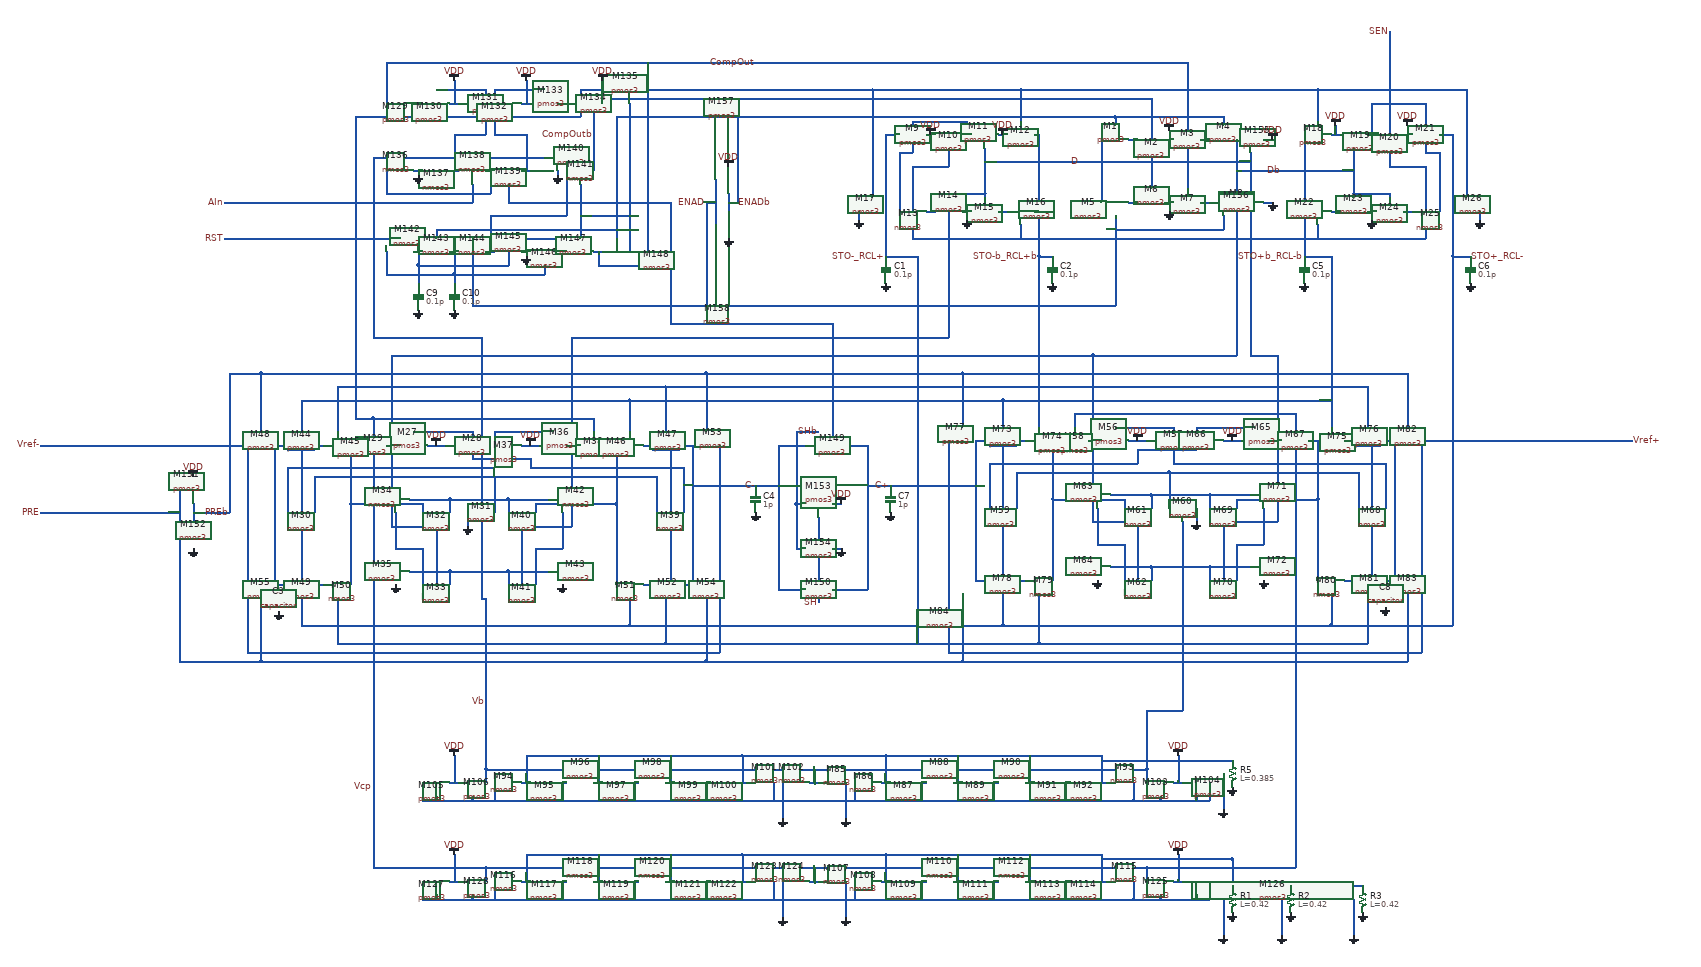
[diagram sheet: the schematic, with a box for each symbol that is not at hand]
v {xschem version=3.4.3 file_version=1.2
}
G {}
K {}
V {}
S {}
E {}
N 2570 -1810 2590 -1810 {
lab=#net1}
N 2650 -1810 2670 -1810 {
lab=VDD}
N 2730 -1810 2750 -1810 {
lab=#net2}
N 2570 -1670 2590 -1670 {
lab=#net3}
N 2650 -1670 2670 -1670 {
lab=GND}
N 2730 -1670 2750 -1670 {
lab=#net4}
N 2620 -1780 2620 -1700 {
lab=CompOutb}
N 2700 -1780 2700 -1700 {
lab=CompOut}
N 2660 -1830 2660 -1810 {
lab=VDD}
N 2660 -1670 2660 -1650 {
lab=GND}
N 2540 -1860 2540 -1840 {
lab=ENADb}
N 2540 -1640 2540 -1600 {
lab=ENAD}
N 2510 -1810 2510 -1670 {
lab=D}
N 2810 -1810 2810 -1670 {
lab=Db}
N 2120 -1820 2140 -1820 {
lab=VDD}
N 2200 -1820 2220 -1820 {
lab=#net5}
N 2280 -1820 2300 -1820 {
lab=VDD}
N 2090 -1790 2090 -1780 {
lab=#net5}
N 2120 -1650 2140 -1650 {
lab=#net6}
N 2200 -1650 2220 -1650 {
lab=GND}
N 2280 -1650 2300 -1650 {
lab=#net7}
N 2210 -1650 2210 -1630 {
lab=GND}
N 1970 -1650 1970 -1630 {
lab=GND}
N 2170 -1690 2170 -1680 {
lab=D}
N 2170 -1690 2250 -1690 {
lab=D}
N 2250 -1690 2250 -1680 {
lab=D}
N 2090 -1620 2090 -1590 {
lab=SEN}
N 2090 -1590 2330 -1590 {
lab=SEN}
N 2330 -1620 2330 -1590 {
lab=SEN}
N 2030 -1820 2030 -1650 {
lab=STO-_RCL+}
N 2060 -1780 2060 -1650 {
lab=#net5}
N 2060 -1780 2090 -1780 {
lab=#net5}
N 2030 -1820 2060 -1820 {
lab=STO-_RCL+}
N 2250 -1790 2250 -1690 {
lab=D}
N 2090 -1750 2090 -1620 {
lab=SEN}
N 2090 -1750 2170 -1750 {
lab=SEN}
N 2170 -1790 2170 -1750 {
lab=SEN}
N 2000 -1920 2000 -1680 {
lab=Vcp}
N 2000 -1920 2330 -1920 {
lab=Vcp}
N 2330 -1920 2330 -1850 {
lab=Vcp}
N 2030 -1650 2030 -1550 {
lab=STO-_RCL+}
N 3020 -1820 3040 -1820 {
lab=VDD}
N 3100 -1820 3120 -1820 {
lab=#net8}
N 3180 -1820 3200 -1820 {
lab=VDD}
N 3030 -1840 3030 -1820 {
lab=VDD}
N 3190 -1840 3190 -1820 {
lab=VDD}
N 3020 -1650 3040 -1650 {
lab=#net9}
N 3100 -1650 3120 -1650 {
lab=GND}
N 3180 -1650 3200 -1650 {
lab=#net10}
N 3110 -1650 3110 -1630 {
lab=GND}
N 3070 -1690 3070 -1680 {
lab=Db}
N 3070 -1690 3150 -1690 {
lab=Db}
N 3150 -1690 3150 -1680 {
lab=Db}
N 2990 -1620 2990 -1590 {
lab=SEN}
N 2990 -1590 3230 -1590 {
lab=SEN}
N 3230 -1620 3230 -1590 {
lab=SEN}
N 3110 -1890 3110 -1820 {
lab=#net8}
N 3350 -1650 3350 -1630 {
lab=GND}
N 3110 -1890 3230 -1890 {
lab=#net8}
N 3230 -1890 3230 -1790 {
lab=#net8}
N 3260 -1820 3290 -1820 {
lab=STO+_RCL-}
N 3290 -1820 3290 -1650 {
lab=STO+_RCL-}
N 3290 -1650 3290 -1550 {
lab=STO+_RCL-}
N 2960 -1650 2960 -1550 {
lab=STO+b_RCL-b}
N 3070 -1790 3070 -1690 {
lab=Db}
N 3230 -1790 3230 -1780 {
lab=#net8}
N 3260 -1780 3260 -1650 {
lab=#net8}
N 3230 -1780 3260 -1780 {
lab=#net8}
N 3230 -1750 3230 -1620 {
lab=SEN}
N 3150 -1750 3230 -1750 {
lab=SEN}
N 3150 -1790 3150 -1750 {
lab=SEN}
N 3320 -1910 3320 -1680 {
lab=Vcp}
N 3320 -1920 3320 -1910 {
lab=Vcp}
N 2990 -1920 3320 -1920 {
lab=Vcp}
N 2990 -1920 2990 -1850 {
lab=Vcp}
N 2960 -1820 2960 -1650 {
lab=STO+b_RCL-b}
N 2810 -1740 3070 -1740 {
lab=Db}
N 2330 -1920 2990 -1920 {
lab=Vcp}
N 2330 -1590 2990 -1590 {
lab=SEN}
N 1010 -1130 1050 -1130 {
lab=VDD}
N 980 -1160 1080 -1160 {
lab=#net11}
N 1030 -950 1030 -820 {
lab=Db}
N 1060 -1010 1060 -980 {
lab=#net12}
N 970 -1010 1060 -1010 {
lab=#net12}
N 970 -850 1060 -850 {
lab=#net13}
N 1060 -850 1060 -820 {
lab=#net13}
N 940 -980 940 -900 {
lab=#net14}
N 940 -900 1000 -900 {
lab=#net14}
N 1220 -1130 1260 -1130 {
lab=VDD}
N 1190 -1160 1290 -1160 {
lab=#net15}
N 1320 -1130 1350 -1130 {
lab=#net16}
N 1220 -950 1220 -820 {
lab=D}
N 1190 -1010 1280 -1010 {
lab=#net12}
N 1190 -850 1280 -850 {
lab=#net13}
N 1310 -980 1310 -900 {
lab=#net17}
N 1250 -900 1310 -900 {
lab=#net17}
N 700 -1120 760 -1120 {
lab=#net18}
N 760 -1130 760 -1120 {
lab=#net18}
N 700 -830 700 -820 {
lab=#net18}
N 700 -830 760 -830 {
lab=#net18}
N 760 -830 760 -820 {
lab=#net18}
N 730 -1120 730 -1020 {
lab=#net18}
N 730 -1020 730 -830 {
lab=#net18}
N 1510 -1130 1510 -1120 {
lab=C-}
N 1510 -1120 1570 -1120 {
lab=C-}
N 1570 -1130 1570 -1120 {
lab=C-}
N 1510 -830 1510 -820 {
lab=C-}
N 1510 -830 1570 -830 {
lab=C-}
N 1570 -830 1570 -820 {
lab=C-}
N 1550 -1120 1550 -1020 {
lab=C-}
N 1550 -1020 1550 -830 {
lab=C-}
N 760 -1130 780 -1130 {
lab=#net18}
N 760 -820 780 -820 {
lab=#net18}
N 1490 -1130 1510 -1130 {
lab=C-}
N 1490 -820 1510 -820 {
lab=C-}
N 1430 -1130 1430 -1040 {
lab=#net19}
N 1430 -960 1430 -820 {
lab=#net19}
N 1250 -1000 1250 -980 {
lab=#net19}
N 1250 -1000 1430 -1000 {
lab=#net19}
N 1430 -1040 1430 -1000 {
lab=#net19}
N 1000 -1000 1000 -980 {
lab=#net20}
N 840 -1000 1000 -1000 {
lab=#net20}
N 840 -1130 840 -1000 {
lab=#net20}
N 840 -1000 840 -820 {
lab=#net20}
N 1430 -1000 1430 -960 {
lab=#net19}
N 840 -1130 860 -1130 {
lab=#net20}
N 760 -1080 980 -1080 {
lab=#net15}
N 1290 -1080 1520 -1080 {
lab=#net11}
N 1080 -1160 1110 -1160 {
lab=#net11}
N 1110 -1160 1110 -1130 {
lab=#net11}
N 1160 -1160 1160 -1130 {
lab=#net15}
N 1160 -1160 1190 -1160 {
lab=#net15}
N 670 -1130 670 -820 {
lab=#net18}
N 1600 -1130 1600 -820 {
lab=C-}
N 610 -1130 610 -820 {
lab=Vref-}
N 1660 -1130 1660 -820 {
lab=Vref-}
N 1190 -850 1190 -820 {
lab=#net13}
N 1190 -1010 1190 -980 {
lab=#net12}
N 700 -1080 760 -1080 {
lab=#net15}
N 700 -1080 700 -980 {
lab=#net15}
N 1520 -1080 1580 -1080 {
lab=#net11}
N 1580 -1080 1580 -980 {
lab=#net11}
N 760 -1060 760 -980 {
lab=#net21}
N 760 -1060 1100 -1060 {
lab=#net21}
N 1100 -1060 1520 -1060 {
lab=#net21}
N 1520 -1060 1520 -980 {
lab=#net21}
N 1000 -900 1000 -820 {
lab=#net14}
N 1250 -900 1250 -820 {
lab=#net17}
N 1030 -820 1030 -790 {
lab=Db}
N 1220 -820 1220 -790 {
lab=D}
N 1130 -950 1130 -790 {
lab=Vb}
N 1410 -1130 1430 -1130 {
lab=#net19}
N 700 -1130 700 -1120 {
lab=#net18}
N 670 -1130 700 -1130 {
lab=#net18}
N 670 -820 700 -820 {
lab=#net18}
N 1570 -1130 1600 -1130 {
lab=C-}
N 1570 -820 1600 -820 {
lab=C-}
N 1060 -1010 1190 -1010 {
lab=#net12}
N 1060 -850 1190 -850 {
lab=#net13}
N 2570 -1140 2610 -1140 {
lab=VDD}
N 2540 -1170 2640 -1170 {
lab=#net22}
N 2480 -1140 2510 -1140 {
lab=#net23}
N 2590 -960 2590 -830 {
lab=Db}
N 2620 -1020 2620 -990 {
lab=#net24}
N 2530 -1020 2620 -1020 {
lab=#net24}
N 2530 -860 2620 -860 {
lab=#net25}
N 2620 -860 2620 -830 {
lab=#net25}
N 2500 -990 2500 -910 {
lab=#net26}
N 2500 -910 2560 -910 {
lab=#net26}
N 2780 -1140 2820 -1140 {
lab=VDD}
N 2750 -1170 2850 -1170 {
lab=#net27}
N 2880 -1140 2910 -1140 {
lab=#net28}
N 2780 -960 2780 -830 {
lab=D}
N 2750 -1020 2840 -1020 {
lab=#net24}
N 2750 -860 2840 -860 {
lab=#net25}
N 2870 -990 2870 -910 {
lab=#net29}
N 2810 -910 2870 -910 {
lab=#net29}
N 2260 -1130 2320 -1130 {
lab=C+}
N 2320 -1140 2320 -1130 {
lab=C+}
N 2260 -840 2260 -830 {
lab=C+}
N 2260 -840 2320 -840 {
lab=C+}
N 2320 -840 2320 -830 {
lab=C+}
N 2290 -1130 2290 -1030 {
lab=C+}
N 2290 -1030 2290 -840 {
lab=C+}
N 3070 -1140 3070 -1130 {
lab=#net30}
N 3070 -1130 3130 -1130 {
lab=#net30}
N 3130 -1140 3130 -1130 {
lab=#net30}
N 3070 -840 3070 -830 {
lab=#net30}
N 3070 -840 3130 -840 {
lab=#net30}
N 3130 -840 3130 -830 {
lab=#net30}
N 3110 -1130 3110 -1030 {
lab=#net30}
N 3110 -1030 3110 -840 {
lab=#net30}
N 2320 -1140 2340 -1140 {
lab=C+}
N 2320 -830 2340 -830 {
lab=C+}
N 3050 -1140 3070 -1140 {
lab=#net30}
N 3050 -830 3070 -830 {
lab=#net30}
N 2990 -1140 2990 -1050 {
lab=#net31}
N 2990 -970 2990 -830 {
lab=#net31}
N 2810 -1010 2810 -990 {
lab=#net31}
N 2810 -1010 2990 -1010 {
lab=#net31}
N 2990 -1050 2990 -1010 {
lab=#net31}
N 2560 -1010 2560 -990 {
lab=#net32}
N 2400 -1010 2560 -1010 {
lab=#net32}
N 2400 -1140 2400 -1010 {
lab=#net32}
N 2400 -1010 2400 -830 {
lab=#net32}
N 2990 -1010 2990 -970 {
lab=#net31}
N 2400 -1140 2420 -1140 {
lab=#net32}
N 2320 -1090 2540 -1090 {
lab=#net27}
N 2850 -1090 3080 -1090 {
lab=#net22}
N 2640 -1170 2670 -1170 {
lab=#net22}
N 2670 -1170 2670 -1140 {
lab=#net22}
N 2720 -1170 2720 -1140 {
lab=#net27}
N 2720 -1170 2750 -1170 {
lab=#net27}
N 2230 -1140 2230 -830 {
lab=C+}
N 3160 -1140 3160 -830 {
lab=#net30}
N 2170 -1140 2170 -830 {
lab=Vref+}
N 3220 -1140 3220 -830 {
lab=Vref+}
N 2750 -860 2750 -830 {
lab=#net25}
N 2750 -1020 2750 -990 {
lab=#net24}
N 2260 -1090 2320 -1090 {
lab=#net27}
N 2260 -1090 2260 -990 {
lab=#net27}
N 3080 -1090 3140 -1090 {
lab=#net22}
N 3140 -1090 3140 -990 {
lab=#net22}
N 2320 -1070 2320 -990 {
lab=#net33}
N 2320 -1070 2660 -1070 {
lab=#net33}
N 2660 -1070 2660 -990 {
lab=#net33}
N 2660 -1070 3080 -1070 {
lab=#net33}
N 3080 -1070 3080 -990 {
lab=#net33}
N 2560 -910 2560 -830 {
lab=#net26}
N 2810 -910 2810 -830 {
lab=#net29}
N 2590 -830 2590 -800 {
lab=Db}
N 2780 -830 2780 -800 {
lab=D}
N 2690 -960 2690 -800 {
lab=Vb}
N 2970 -1140 2990 -1140 {
lab=#net31}
N 2260 -1140 2260 -1130 {
lab=C+}
N 2230 -1140 2260 -1140 {
lab=C+}
N 2230 -830 2260 -830 {
lab=C+}
N 3130 -1140 3160 -1140 {
lab=#net30}
N 3130 -830 3160 -830 {
lab=#net30}
N 2620 -1020 2750 -1020 {
lab=#net24}
N 2620 -860 2750 -860 {
lab=#net25}
N 2020 -380 2040 -380 {
lab=#net34}
N 2100 -380 2120 -380 {
lab=#net35}
N 2180 -380 2200 -380 {
lab=#net34}
N 2260 -380 2280 -380 {
lab=#net35}
N 2340 -380 2360 -380 {
lab=#net34}
N 2420 -380 2440 -380 {
lab=#net35}
N 2500 -380 2520 -380 {
lab=#net34}
N 1220 -380 1240 -380 {
lab=#net34}
N 1300 -380 1320 -380 {
lab=#net35}
N 1380 -380 1400 -380 {
lab=#net34}
N 1460 -380 1480 -380 {
lab=#net35}
N 1540 -380 1560 -380 {
lab=#net34}
N 1620 -380 1640 -380 {
lab=#net35}
N 1700 -380 1720 -380 {
lab=#net34}
N 1860 -380 1880 -380 {
lab=Vb}
N 1190 -410 2550 -410 {
lab=Vb}
N 1780 -380 1780 -340 {
lab=#net35}
N 1160 -340 1780 -340 {
lab=#net35}
N 1160 -380 1160 -340 {
lab=#net35}
N 1470 -380 1470 -340 {
lab=#net35}
N 1310 -380 1310 -340 {
lab=#net35}
N 1630 -380 1630 -340 {
lab=#net35}
N 1230 -440 1230 -380 {
lab=#net34}
N 1230 -440 1710 -440 {
lab=#net34}
N 1710 -440 1710 -380 {
lab=#net34}
N 1550 -440 1550 -380 {
lab=#net34}
N 1390 -440 1390 -380 {
lab=#net34}
N 1960 -380 1960 -340 {
lab=#net35}
N 1960 -340 2580 -340 {
lab=#net35}
N 2580 -380 2580 -340 {
lab=#net35}
N 2270 -380 2270 -340 {
lab=#net35}
N 2110 -380 2110 -340 {
lab=#net35}
N 2430 -380 2430 -340 {
lab=#net35}
N 2030 -440 2030 -380 {
lab=#net34}
N 2030 -440 2510 -440 {
lab=#net34}
N 2510 -440 2510 -380 {
lab=#net34}
N 2350 -440 2350 -380 {
lab=#net34}
N 2190 -440 2190 -380 {
lab=#net34}
N 1710 -440 2030 -440 {
lab=#net34}
N 1780 -340 1960 -340 {
lab=#net35}
N 1870 -410 1870 -380 {
lab=Vb}
N 1800 -380 1800 -300 {
lab=GND}
N 1940 -380 1940 -300 {
lab=GND}
N 2670 -380 2690 -380 {
lab=VDD}
N 1060 -380 1080 -380 {
lab=VDD}
N 1070 -440 1070 -380 {
lab=VDD}
N 2680 -440 2680 -380 {
lab=VDD}
N 1140 -410 1140 -380 {
lab=Vb}
N 1140 -410 1190 -410 {
lab=Vb}
N 1110 -350 1110 -340 {
lab=#net35}
N 1110 -340 1160 -340 {
lab=#net35}
N 2640 -350 2640 -340 {
lab=#net35}
N 2580 -340 2640 -340 {
lab=#net35}
N 2610 -410 2610 -380 {
lab=Vb}
N 2550 -410 2610 -410 {
lab=Vb}
N 2640 -340 2750 -340 {
lab=#net35}
N 2720 -350 2720 -340 {
lab=#net35}
N 2750 -380 2750 -340 {
lab=#net35}
N 1000 -340 1110 -340 {
lab=#net35}
N 1000 -380 1000 -340 {
lab=#net35}
N 1030 -350 1030 -340 {
lab=#net35}
N 2510 -430 2800 -430 {
lab=#net34}
N 2020 -160 2040 -160 {
lab=#net36}
N 2100 -160 2120 -160 {
lab=#net37}
N 2180 -160 2200 -160 {
lab=#net36}
N 2260 -160 2280 -160 {
lab=#net37}
N 2340 -160 2360 -160 {
lab=#net36}
N 2420 -160 2440 -160 {
lab=#net37}
N 2500 -160 2520 -160 {
lab=#net36}
N 1220 -160 1240 -160 {
lab=#net36}
N 1300 -160 1320 -160 {
lab=#net37}
N 1380 -160 1400 -160 {
lab=#net36}
N 1460 -160 1480 -160 {
lab=#net37}
N 1540 -160 1560 -160 {
lab=#net36}
N 1620 -160 1640 -160 {
lab=#net37}
N 1700 -160 1720 -160 {
lab=#net36}
N 1860 -160 1880 -160 {
lab=Vcp}
N 1190 -190 2550 -190 {
lab=Vcp}
N 1780 -160 1780 -120 {
lab=#net37}
N 1160 -120 1780 -120 {
lab=#net37}
N 1160 -160 1160 -120 {
lab=#net37}
N 1470 -160 1470 -120 {
lab=#net37}
N 1310 -160 1310 -120 {
lab=#net37}
N 1630 -160 1630 -120 {
lab=#net37}
N 1230 -220 1230 -160 {
lab=#net36}
N 1230 -220 1710 -220 {
lab=#net36}
N 1710 -220 1710 -160 {
lab=#net36}
N 1550 -220 1550 -160 {
lab=#net36}
N 1390 -220 1390 -160 {
lab=#net36}
N 1960 -160 1960 -120 {
lab=#net37}
N 1960 -120 2580 -120 {
lab=#net37}
N 2580 -160 2580 -120 {
lab=#net37}
N 2270 -160 2270 -120 {
lab=#net37}
N 2110 -160 2110 -120 {
lab=#net37}
N 2430 -160 2430 -120 {
lab=#net37}
N 2030 -220 2030 -160 {
lab=#net36}
N 2030 -220 2510 -220 {
lab=#net36}
N 2510 -220 2510 -160 {
lab=#net36}
N 2350 -220 2350 -160 {
lab=#net36}
N 2190 -220 2190 -160 {
lab=#net36}
N 1710 -220 2030 -220 {
lab=#net36}
N 1780 -120 1960 -120 {
lab=#net37}
N 1870 -190 1870 -160 {
lab=Vcp}
N 1800 -160 1800 -80 {
lab=GND}
N 1940 -160 1940 -80 {
lab=GND}
N 2670 -160 2690 -160 {
lab=VDD}
N 1060 -160 1080 -160 {
lab=VDD}
N 1070 -220 1070 -160 {
lab=VDD}
N 2680 -220 2680 -160 {
lab=VDD}
N 1140 -190 1140 -160 {
lab=Vcp}
N 1140 -190 1190 -190 {
lab=Vcp}
N 1110 -130 1110 -120 {
lab=#net37}
N 1110 -120 1160 -120 {
lab=#net37}
N 2640 -130 2640 -120 {
lab=#net37}
N 2580 -120 2640 -120 {
lab=#net37}
N 2610 -190 2610 -160 {
lab=Vcp}
N 2550 -190 2610 -190 {
lab=Vcp}
N 2640 -120 2750 -120 {
lab=#net37}
N 2720 -130 2720 -120 {
lab=#net37}
N 2750 -160 2750 -120 {
lab=#net37}
N 1000 -120 1110 -120 {
lab=#net37}
N 1000 -160 1000 -120 {
lab=#net37}
N 1030 -130 1030 -120 {
lab=#net37}
N 2510 -210 2800 -210 {
lab=#net36}
N 2610 -480 2610 -410 {
lab=Vb}
N 980 -1890 1000 -1890 {
lab=#net38}
N 1060 -1890 1080 -1890 {
lab=VDD}
N 1220 -1890 1240 -1890 {
lab=VDD}
N 1300 -1890 1320 -1890 {
lab=#net39}
N 1030 -1920 1110 -1920 {
lab=#net40}
N 1190 -1920 1270 -1920 {
lab=#net41}
N 1140 -1920 1140 -1890 {
lab=#net40}
N 1110 -1920 1140 -1920 {
lab=#net40}
N 1160 -1920 1160 -1890 {
lab=#net41}
N 1160 -1920 1190 -1920 {
lab=#net41}
N 950 -1860 1350 -1860 {
lab=Vcp}
N 980 -1740 1000 -1740 {
lab=GND}
N 1140 -1740 1160 -1740 {
lab=#net42}
N 1060 -1740 1080 -1740 {
lab=#net40}
N 1220 -1740 1240 -1740 {
lab=#net41}
N 980 -1560 1000 -1560 {
lab=#net43}
N 1140 -1560 1160 -1560 {
lab=#net44}
N 1060 -1560 1080 -1560 {
lab=#net45}
N 1220 -1560 1240 -1560 {
lab=GND}
N 1300 -1560 1320 -1560 {
lab=#net43}
N 1380 -1560 1400 -1560 {
lab=CompOut}
N 1380 -1890 1380 -1740 {
lab=CompOutb}
N 1460 -1690 1460 -1560 {
lab=#net46}
N 1430 -1860 1430 -1590 {
lab=ENADb}
N 1460 -1890 1460 -1690 {
lab=#net46}
N 1350 -1710 1350 -1590 {
lab=#net46}
N 1350 -1640 1460 -1640 {
lab=#net46}
N 1150 -1640 1150 -1560 {
lab=#net44}
N 1150 -1640 1320 -1640 {
lab=#net44}
N 1320 -1740 1320 -1640 {
lab=#net44}
N 920 -1560 920 -1530 {
lab=#net45}
N 920 -1530 920 -1510 {
lab=#net45}
N 920 -1510 1070 -1510 {
lab=#net45}
N 1190 -1590 1310 -1590 {
lab=#net43}
N 1310 -1590 1310 -1560 {
lab=#net43}
N 1070 -1510 1270 -1510 {
lab=#net45}
N 1270 -1530 1270 -1510 {
lab=#net45}
N 1230 -1560 1230 -1550 {
lab=GND}
N 1190 -1590 1190 -1530 {
lab=#net43}
N 990 -1530 1190 -1530 {
lab=#net43}
N 1070 -1560 1070 -1510 {
lab=#net45}
N 1070 -1510 1070 -1490 {
lab=#net45}
N 990 -1560 990 -1530 {
lab=#net43}
N 990 -1530 990 -1490 {
lab=#net43}
N 1140 -1890 1140 -1820 {
lab=#net40}
N 1070 -1820 1140 -1820 {
lab=#net40}
N 1070 -1820 1070 -1740 {
lab=#net40}
N 1160 -1890 1160 -1820 {
lab=#net41}
N 1160 -1820 1230 -1820 {
lab=#net41}
N 1230 -1820 1230 -1740 {
lab=#net41}
N 990 -1740 990 -1730 {
lab=GND}
N 920 -1740 920 -1690 {
lab=#net42}
N 920 -1690 1150 -1690 {
lab=#net42}
N 1150 -1740 1150 -1690 {
lab=#net42}
N 1300 -1740 1300 -1730 {
lab=GND}
N 950 -1770 1270 -1770 {
lab=Vb}
N 1070 -1940 1070 -1890 {
lab=VDD}
N 1230 -1940 1230 -1890 {
lab=VDD}
N 1400 -1940 1400 -1890 {
lab=VDD}
N 1030 -1610 1030 -1590 {
lab=ENADb}
N 1030 -1610 1430 -1610 {
lab=ENADb}
N 920 -1130 950 -1130 {
lab=#net47}
N 490 -1000 490 -960 {
lab=PREb}
N 460 -1030 460 -930 {
lab=PRE}
N 490 -980 510 -980 {
lab=PREb}
N 1680 -1690 1680 -1650 {
lab=ENADb}
N 1650 -1720 1650 -1620 {
lab=ENAD}
N 1630 -1670 1650 -1670 {
lab=ENAD}
N 1680 -1670 1700 -1670 {
lab=ENADb}
N 560 -1590 950 -1590 {
lab=RST}
N 150 -1130 610 -1130 {
lab=Vref-}
N 3220 -1140 3690 -1140 {
lab=Vref+}
N 890 -1190 890 -1160 {
lab=Vcp}
N 890 -1190 1380 -1190 {
lab=Vcp}
N 1380 -1190 1380 -1160 {
lab=Vcp}
N 890 -1860 950 -1860 {
lab=Vcp}
N 2450 -1200 2450 -1170 {
lab=Vcp}
N 2450 -1200 2940 -1200 {
lab=Vcp}
N 2940 -1200 2940 -1170 {
lab=Vcp}
N 890 -190 1140 -190 {
lab=Vcp}
N 1350 -1920 1350 -1860 {
lab=Vcp}
N 1350 -1920 2000 -1920 {
lab=Vcp}
N 2800 -210 2800 -150 {
lab=#net36}
N 2610 -190 2940 -190 {
lab=Vcp}
N 890 -1160 890 -190 {
lab=Vcp}
N 2940 -1170 2940 -190 {
lab=Vcp}
N 980 -1080 1160 -1080 {
lab=#net15}
N 1160 -1130 1160 -1080 {
lab=#net15}
N 1240 -1080 1290 -1080 {
lab=#net11}
N 1240 -1100 1240 -1080 {
lab=#net11}
N 1110 -1100 1240 -1100 {
lab=#net11}
N 1110 -1130 1110 -1100 {
lab=#net11}
N 2670 -1090 2850 -1090 {
lab=#net22}
N 2670 -1140 2670 -1090 {
lab=#net22}
N 2540 -1090 2590 -1090 {
lab=#net27}
N 2590 -1120 2590 -1090 {
lab=#net27}
N 2590 -1120 2720 -1120 {
lab=#net27}
N 2720 -1140 2720 -1120 {
lab=#net27}
N 3150 -2050 3150 -1790 {
lab=SEN}
N 1880 -970 1880 -780 {
lab=SH}
N 1830 -900 1850 -900 {
lab=SHb}
N 1830 -1000 1830 -900 {
lab=SHb}
N 1830 -1000 1850 -1000 {
lab=SHb}
N 1830 -1160 1830 -1000 {
lab=SHb}
N 1830 -1160 1880 -1160 {
lab=SHb}
N 1790 -1130 1790 -1060 {
lab=C-}
N 1790 -1130 1850 -1130 {
lab=C-}
N 1790 -1060 1790 -810 {
lab=C-}
N 1790 -810 1850 -810 {
lab=C-}
N 1910 -1000 1930 -1000 {
lab=VDD}
N 1910 -900 1930 -900 {
lab=GND}
N 1910 -810 1990 -810 {
lab=C+}
N 1990 -1130 1990 -810 {
lab=C+}
N 1600 -1040 1790 -1040 {
lab=C-}
N 2720 -990 2720 -960 {
lab=GND}
N 2690 -800 2690 -540 {
lab=Vb}
N 2610 -540 2690 -540 {
lab=Vb}
N 2610 -540 2610 -480 {
lab=Vb}
N 1100 -980 1100 -950 {
lab=GND}
N 1140 -790 1140 -410 {
lab=Vb}
N 1130 -790 1140 -790 {
lab=Vb}
N 1110 -1710 1110 -1670 {
lab=AIn}
N 560 -1670 1110 -1670 {
lab=AIn}
N 1190 -1710 1190 -1670 {
lab=C+}
N 1190 -1670 1550 -1670 {
lab=C+}
N 3290 -1550 3330 -1550 {
lab=STO+_RCL-}
N 3290 -1550 3290 -770 {
lab=STO+_RCL-}
N 1910 -1130 1990 -1130 {
lab=C+}
N 1990 -1040 2230 -1040 {
lab=C+}
N 3290 -770 3290 -730 {
lab=STO+_RCL-}
N 3020 -730 3290 -730 {
lab=STO+_RCL-}
N 3020 -800 3020 -730 {
lab=STO+_RCL-}
N 2290 -730 3020 -730 {
lab=STO+_RCL-}
N 2290 -800 2290 -730 {
lab=STO+_RCL-}
N 1460 -730 2290 -730 {
lab=STO+_RCL-}
N 1460 -790 1460 -730 {
lab=STO+_RCL-}
N 730 -730 1460 -730 {
lab=STO+_RCL-}
N 730 -790 730 -730 {
lab=STO+_RCL-}
N 1130 -1370 1130 -950 {
lab=Vb}
N 910 -1370 1130 -1370 {
lab=Vb}
N 890 -1370 910 -1370 {
lab=Vb}
N 890 -1770 890 -1370 {
lab=Vb}
N 890 -1770 950 -1770 {
lab=Vb}
N 850 -1860 890 -1860 {
lab=Vcp}
N 850 -1860 850 -1190 {
lab=Vcp}
N 850 -1190 890 -1190 {
lab=Vcp}
N 810 -790 810 -690 {
lab=STO-_RCL+}
N 810 -690 1540 -690 {
lab=STO-_RCL+}
N 1540 -790 1540 -690 {
lab=STO-_RCL+}
N 1540 -690 2370 -690 {
lab=STO-_RCL+}
N 2370 -800 2370 -690 {
lab=STO-_RCL+}
N 2370 -690 3100 -690 {
lab=STO-_RCL+}
N 3100 -800 3100 -690 {
lab=STO-_RCL+}
N 2100 -1550 2100 -690 {
lab=STO-_RCL+}
N 2030 -1550 2100 -1550 {
lab=STO-_RCL+}
N 920 -1980 920 -1890 {
lab=CompOut}
N 920 -1980 2700 -1980 {
lab=CompOut}
N 2700 -1980 2700 -1780 {
lab=CompOut}
N 1390 -1530 1500 -1530 {
lab=CompOut}
N 1500 -1980 1500 -1530 {
lab=CompOut}
N 1390 -1560 1390 -1530 {
lab=CompOut}
N 1380 -1900 1380 -1890 {
lab=CompOutb}
N 1380 -1900 2620 -1900 {
lab=CompOutb}
N 2620 -1900 2620 -1780 {
lab=CompOutb}
N 3020 -1550 3020 -1170 {
lab=STO+b_RCL-b}
N 2960 -1550 3020 -1550 {
lab=STO+b_RCL-b}
N 2290 -1230 2290 -1170 {
lab=STO+b_RCL-b}
N 2290 -1230 3020 -1230 {
lab=STO+b_RCL-b}
N 1460 -1230 2290 -1230 {
lab=STO+b_RCL-b}
N 1460 -1230 1460 -1160 {
lab=STO+b_RCL-b}
N 730 -1230 1460 -1230 {
lab=STO+b_RCL-b}
N 730 -1230 730 -1160 {
lab=STO+b_RCL-b}
N 2360 -1260 3100 -1260 {
lab=STO-b_RCL+b}
N 3100 -1260 3100 -1170 {
lab=STO-b_RCL+b}
N 1540 -1260 2360 -1260 {
lab=STO-b_RCL+b}
N 1540 -1260 1540 -1160 {
lab=STO-b_RCL+b}
N 810 -1260 1540 -1260 {
lab=STO-b_RCL+b}
N 810 -1260 810 -1160 {
lab=STO-b_RCL+b}
N 640 -790 640 -650 {
lab=PRE}
N 640 -650 1630 -650 {
lab=PRE}
N 1630 -790 1630 -650 {
lab=PRE}
N 460 -930 460 -650 {
lab=PRE}
N 460 -650 640 -650 {
lab=PRE}
N 150 -980 460 -980 {
lab=PRE}
N 1630 -650 2200 -650 {
lab=PRE}
N 2200 -800 2200 -650 {
lab=PRE}
N 2200 -650 3190 -650 {
lab=PRE}
N 3190 -800 3190 -650 {
lab=PRE}
N 640 -1290 640 -1160 {
lab=PREb}
N 640 -1290 1630 -1290 {
lab=PREb}
N 1630 -1290 1630 -1160 {
lab=PREb}
N 1630 -1290 2200 -1290 {
lab=PREb}
N 2200 -1290 2200 -1170 {
lab=PREb}
N 2200 -1290 3190 -1290 {
lab=PREb}
N 3190 -1290 3190 -1170 {
lab=PREb}
N 570 -1290 640 -1290 {
lab=PREb}
N 570 -1290 570 -980 {
lab=PREb}
N 510 -980 570 -980 {
lab=PREb}
N 610 -820 610 -670 {
lab=Vref-}
N 610 -670 1660 -670 {
lab=Vref-}
N 1660 -820 1660 -670 {
lab=Vref-}
N 2170 -830 2170 -670 {
lab=Vref+}
N 2170 -670 3220 -670 {
lab=Vref+}
N 3220 -830 3220 -670 {
lab=Vref+}
N 2090 -1850 2090 -1790 {
lab=#net5}
N 2090 -1850 2210 -1850 {
lab=#net5}
N 2210 -1850 2210 -1820 {
lab=#net5}
N 1430 -1860 2540 -1860 {
lab=ENADb}
N 2780 -1860 2780 -1840 {
lab=ENADb}
N 2540 -1860 2780 -1860 {
lab=ENADb}
N 2540 -1600 2540 -1440 {
lab=ENAD}
N 1110 -1440 2540 -1440 {
lab=ENAD}
N 1110 -1590 1110 -1440 {
lab=ENAD}
N 2540 -1610 2780 -1610 {
lab=ENAD}
N 2780 -1640 2780 -1610 {
lab=ENAD}
N 1550 -1670 1550 -1400 {
lab=C+}
N 1550 -1400 1910 -1400 {
lab=C+}
N 1910 -1400 1910 -1130 {
lab=C+}
N 1700 -1860 1700 -1670 {
lab=ENADb}
N 1630 -1670 1630 -1440 {
lab=ENAD}
N 2370 -1260 2370 -1170 {
lab=STO-b_RCL+b}
N 2370 -1550 2370 -1260 {
lab=STO-b_RCL+b}
N 2370 -1820 2370 -1550 {
lab=STO-b_RCL+b}
N 2360 -1820 2370 -1820 {
lab=STO-b_RCL+b}
N 2360 -1650 2370 -1650 {
lab=STO-b_RCL+b}
N 2370 -1550 2400 -1550 {
lab=STO-b_RCL+b}
N 1160 -1060 1160 -980 {
lab=#net21}
N 2870 -1810 2890 -1810 {
lab=VDD}
N 2870 -1670 2890 -1670 {
lab=GND}
N 2840 -1780 2840 -1700 {
lab=D}
N 2510 -1760 2840 -1760 {
lab=D}
N 2250 -1760 2510 -1760 {
lab=D}
N 1220 -950 1330 -950 {
lab=D}
N 930 -950 1030 -950 {
lab=Db}
N 930 -1330 930 -950 {
lab=Db}
N 2490 -960 2590 -960 {
lab=Db}
N 2780 -960 2900 -960 {
lab=D}
N 2900 -1330 2900 -960 {
lab=D}
N 2840 -1330 2900 -1330 {
lab=D}
N 2840 -1700 2840 -1330 {
lab=D}
N 930 -1330 1220 -1330 {
lab=Db}
N 1220 -1330 2490 -1330 {
lab=Db}
N 2490 -1330 2810 -1330 {
lab=Db}
N 2810 -1670 2810 -1330 {
lab=Db}
N 2490 -1330 2490 -960 {
lab=Db}
N 1330 -1370 1330 -950 {
lab=D}
N 1330 -1370 2170 -1370 {
lab=D}
N 2170 -1680 2170 -1370 {
lab=D}
N 2800 -210 2800 -150 {
lab=#net3}
N 2780 -400 2780 -370 {
lab=GND}
N 2780 -370 2780 -320 {
lab=GND}
N 2780 -90 2780 -40 {
lab=GND}
N 2780 -120 2780 -90 {
lab=GND}
N 2910 -90 2910 -40 {
lab=GND}
N 2910 -120 2910 -90 {
lab=GND}
N 3070 -90 3070 -40 {
lab=GND}
N 3070 -120 3070 -90 {
lab=GND}
N 2800 -150 2930 -150 {
lab=#net3}
N 2930 -150 3090 -150 {
lab=#net3}
C {madvlsi/pmos3.sym} 2540 -1810 1 0 {name=M1
L=0.15
W=1
body=VDD
nf=1
mult=1
ad="'int((nf+1)/2) * W/nf * 0.29'" 
pd="'2*int((nf+1)/2) * (W/nf + 0.29)'"
as="'int((nf+2)/2) * W/nf * 0.29'" 
ps="'2*int((nf+2)/2) * (W/nf + 0.29)'"
nrd="'0.29 / W'" nrs="'0.29 / W'"
sa=0 sb=0 sd=0
model=pfet_01v8
spiceprefix=X
}
C {madvlsi/pmos3.sym} 2620 -1810 3 0 {name=M2
L=0.15
W=1
body=VDD
nf=1
mult=1
ad="'int((nf+1)/2) * W/nf * 0.29'" 
pd="'2*int((nf+1)/2) * (W/nf + 0.29)'"
as="'int((nf+2)/2) * W/nf * 0.29'" 
ps="'2*int((nf+2)/2) * (W/nf + 0.29)'"
nrd="'0.29 / W'" nrs="'0.29 / W'"
sa=0 sb=0 sd=0
model=pfet_01v8
spiceprefix=X
}
C {madvlsi/pmos3.sym} 2700 -1810 3 0 {name=M3
L=0.15
W=1
body=VDD
nf=1
mult=1
ad="'int((nf+1)/2) * W/nf * 0.29'" 
pd="'2*int((nf+1)/2) * (W/nf + 0.29)'"
as="'int((nf+2)/2) * W/nf * 0.29'" 
ps="'2*int((nf+2)/2) * (W/nf + 0.29)'"
nrd="'0.29 / W'" nrs="'0.29 / W'"
sa=0 sb=0 sd=0
model=pfet_01v8
spiceprefix=X
}
C {madvlsi/pmos3.sym} 2780 -1810 1 0 {name=M4
L=0.15
W=1
body=VDD
nf=1
mult=1
ad="'int((nf+1)/2) * W/nf * 0.29'" 
pd="'2*int((nf+1)/2) * (W/nf + 0.29)'"
as="'int((nf+2)/2) * W/nf * 0.29'" 
ps="'2*int((nf+2)/2) * (W/nf + 0.29)'"
nrd="'0.29 / W'" nrs="'0.29 / W'"
sa=0 sb=0 sd=0
model=pfet_01v8
spiceprefix=X
}
C {madvlsi/nmos3.sym} 2540 -1670 3 0 {name=M5
L=0.15
W=1
body=GND
nf=1
mult=1
ad="'int((nf+1)/2) * W/nf * 0.29'" 
pd="'2*int((nf+1)/2) * (W/nf + 0.29)'"
as="'int((nf+2)/2) * W/nf * 0.29'" 
ps="'2*int((nf+2)/2) * (W/nf + 0.29)'"
nrd="'0.29 / W'" nrs="'0.29 / W'"
sa=0 sb=0 sd=0
model=nfet_01v8
spiceprefix=X
}
C {madvlsi/nmos3.sym} 2620 -1670 1 0 {name=M6
L=0.15
W=1
body=GND
nf=1
mult=1
ad="'int((nf+1)/2) * W/nf * 0.29'" 
pd="'2*int((nf+1)/2) * (W/nf + 0.29)'"
as="'int((nf+2)/2) * W/nf * 0.29'" 
ps="'2*int((nf+2)/2) * (W/nf + 0.29)'"
nrd="'0.29 / W'" nrs="'0.29 / W'"
sa=0 sb=0 sd=0
model=nfet_01v8
spiceprefix=X
}
C {madvlsi/nmos3.sym} 2700 -1670 1 0 {name=M7
L=0.15
W=1
body=GND
nf=1
mult=1
ad="'int((nf+1)/2) * W/nf * 0.29'" 
pd="'2*int((nf+1)/2) * (W/nf + 0.29)'"
as="'int((nf+2)/2) * W/nf * 0.29'" 
ps="'2*int((nf+2)/2) * (W/nf + 0.29)'"
nrd="'0.29 / W'" nrs="'0.29 / W'"
sa=0 sb=0 sd=0
model=nfet_01v8
spiceprefix=X
}
C {madvlsi/nmos3.sym} 2780 -1670 3 0 {name=M8
L=0.15
W=1
body=GND
nf=1
mult=1
ad="'int((nf+1)/2) * W/nf * 0.29'" 
pd="'2*int((nf+1)/2) * (W/nf + 0.29)'"
as="'int((nf+2)/2) * W/nf * 0.29'" 
ps="'2*int((nf+2)/2) * (W/nf + 0.29)'"
nrd="'0.29 / W'" nrs="'0.29 / W'"
sa=0 sb=0 sd=0
model=nfet_01v8
spiceprefix=X
}
C {madvlsi/vdd.sym} 2660 -1830 0 0 {name=l1 lab=VDD}
C {madvlsi/gnd.sym} 2660 -1650 0 0 {name=l2 lab=GND}
C {devices/lab_pin.sym} 2460 -1760 1 0 {name=p5 sig_type=std_logic lab=D}
C {devices/lab_pin.sym} 2910 -1740 1 0 {name=p6 sig_type=std_logic lab=Db}
C {madvlsi/pmos3.sym} 2090 -1820 3 0 {name=M9
L=0.15
W=1
body=VDD
nf=1
mult=1
ad="'int((nf+1)/2) * W/nf * 0.29'" 
pd="'2*int((nf+1)/2) * (W/nf + 0.29)'"
as="'int((nf+2)/2) * W/nf * 0.29'" 
ps="'2*int((nf+2)/2) * (W/nf + 0.29)'"
nrd="'0.29 / W'" nrs="'0.29 / W'"
sa=0 sb=0 sd=0
model=pfet_01v8
spiceprefix=X
}
C {madvlsi/pmos3.sym} 2170 -1820 3 0 {name=M10
L=0.15
W=1
body=VDD
nf=1
mult=1
ad="'int((nf+1)/2) * W/nf * 0.29'" 
pd="'2*int((nf+1)/2) * (W/nf + 0.29)'"
as="'int((nf+2)/2) * W/nf * 0.29'" 
ps="'2*int((nf+2)/2) * (W/nf + 0.29)'"
nrd="'0.29 / W'" nrs="'0.29 / W'"
sa=0 sb=0 sd=0
model=pfet_01v8
spiceprefix=X
}
C {madvlsi/pmos3.sym} 2250 -1820 3 0 {name=M11
L=0.15
W=1
body=VDD
nf=1
mult=1
ad="'int((nf+1)/2) * W/nf * 0.29'" 
pd="'2*int((nf+1)/2) * (W/nf + 0.29)'"
as="'int((nf+2)/2) * W/nf * 0.29'" 
ps="'2*int((nf+2)/2) * (W/nf + 0.29)'"
nrd="'0.29 / W'" nrs="'0.29 / W'"
sa=0 sb=0 sd=0
model=pfet_01v8
spiceprefix=X
}
C {madvlsi/pmos3.sym} 2330 -1820 1 0 {name=M12
L=0.15
W=1
body=VDD
nf=1
mult=1
ad="'int((nf+1)/2) * W/nf * 0.29'" 
pd="'2*int((nf+1)/2) * (W/nf + 0.29)'"
as="'int((nf+2)/2) * W/nf * 0.29'" 
ps="'2*int((nf+2)/2) * (W/nf + 0.29)'"
nrd="'0.29 / W'" nrs="'0.29 / W'"
sa=0 sb=0 sd=0
model=pfet_01v8
spiceprefix=X
}
C {madvlsi/vdd.sym} 2130 -1820 0 0 {name=l5 lab=VDD}
C {madvlsi/vdd.sym} 2290 -1820 0 0 {name=l6 lab=VDD}
C {madvlsi/nmos3.sym} 2090 -1650 3 0 {name=M13
L=0.15
W=1
body=GND
nf=1
mult=1
ad="'int((nf+1)/2) * W/nf * 0.29'" 
pd="'2*int((nf+1)/2) * (W/nf + 0.29)'"
as="'int((nf+2)/2) * W/nf * 0.29'" 
ps="'2*int((nf+2)/2) * (W/nf + 0.29)'"
nrd="'0.29 / W'" nrs="'0.29 / W'"
sa=0 sb=0 sd=0
model=nfet_01v8
spiceprefix=X
}
C {madvlsi/nmos3.sym} 2170 -1650 1 0 {name=M14
L=0.15
W=1
body=GND
nf=1
mult=1
ad="'int((nf+1)/2) * W/nf * 0.29'" 
pd="'2*int((nf+1)/2) * (W/nf + 0.29)'"
as="'int((nf+2)/2) * W/nf * 0.29'" 
ps="'2*int((nf+2)/2) * (W/nf + 0.29)'"
nrd="'0.29 / W'" nrs="'0.29 / W'"
sa=0 sb=0 sd=0
model=nfet_01v8
spiceprefix=X
}
C {madvlsi/nmos3.sym} 2250 -1650 1 0 {name=M15
L=0.15
W=1
body=GND
nf=1
mult=1
ad="'int((nf+1)/2) * W/nf * 0.29'" 
pd="'2*int((nf+1)/2) * (W/nf + 0.29)'"
as="'int((nf+2)/2) * W/nf * 0.29'" 
ps="'2*int((nf+2)/2) * (W/nf + 0.29)'"
nrd="'0.29 / W'" nrs="'0.29 / W'"
sa=0 sb=0 sd=0
model=nfet_01v8
spiceprefix=X
}
C {madvlsi/nmos3.sym} 2330 -1650 3 0 {name=M16
L=0.15
W=1
body=GND
nf=1
mult=1
ad="'int((nf+1)/2) * W/nf * 0.29'" 
pd="'2*int((nf+1)/2) * (W/nf + 0.29)'"
as="'int((nf+2)/2) * W/nf * 0.29'" 
ps="'2*int((nf+2)/2) * (W/nf + 0.29)'"
nrd="'0.29 / W'" nrs="'0.29 / W'"
sa=0 sb=0 sd=0
model=nfet_01v8
spiceprefix=X
}
C {madvlsi/gnd.sym} 2210 -1630 0 0 {name=l7 lab=GND}
C {madvlsi/nmos3.sym} 2000 -1650 1 0 {name=M17
L=0.15
W=1
body=GND
nf=1
mult=1
ad="'int((nf+1)/2) * W/nf * 0.29'" 
pd="'2*int((nf+1)/2) * (W/nf + 0.29)'"
as="'int((nf+2)/2) * W/nf * 0.29'" 
ps="'2*int((nf+2)/2) * (W/nf + 0.29)'"
nrd="'0.29 / W'" nrs="'0.29 / W'"
sa=0 sb=0 sd=0
model=nfet_01v8
spiceprefix=X
}
C {madvlsi/gnd.sym} 1970 -1630 0 0 {name=l8 lab=GND}
C {madvlsi/capacitor.sym} 2030 -1520 0 0 {name=C1
value=0.1p
m=1}
C {madvlsi/gnd.sym} 2030 -1490 0 0 {name=l9 lab=GND}
C {madvlsi/capacitor.sym} 2400 -1520 0 0 {name=C2
value=0.1p
m=1}
C {madvlsi/gnd.sym} 2400 -1490 0 0 {name=l10 lab=GND}
C {devices/lab_pin.sym} 2030 -1550 0 0 {name=p10 sig_type=std_logic lab=STO-_RCL+}
C {devices/lab_pin.sym} 2370 -1550 0 0 {name=p11 sig_type=std_logic lab=STO-b_RCL+b}
C {devices/lab_pin.sym} 3150 -2050 1 0 {name=p13 sig_type=std_logic lab=SEN}
C {madvlsi/pmos3.sym} 2990 -1820 1 0 {name=M18
L=0.15
W=1
body=VDD
nf=1
mult=1
ad="'int((nf+1)/2) * W/nf * 0.29'" 
pd="'2*int((nf+1)/2) * (W/nf + 0.29)'"
as="'int((nf+2)/2) * W/nf * 0.29'" 
ps="'2*int((nf+2)/2) * (W/nf + 0.29)'"
nrd="'0.29 / W'" nrs="'0.29 / W'"
sa=0 sb=0 sd=0
model=pfet_01v8
spiceprefix=X
}
C {madvlsi/pmos3.sym} 3070 -1820 3 0 {name=M19
L=0.15
W=1
body=VDD
nf=1
mult=1
ad="'int((nf+1)/2) * W/nf * 0.29'" 
pd="'2*int((nf+1)/2) * (W/nf + 0.29)'"
as="'int((nf+2)/2) * W/nf * 0.29'" 
ps="'2*int((nf+2)/2) * (W/nf + 0.29)'"
nrd="'0.29 / W'" nrs="'0.29 / W'"
sa=0 sb=0 sd=0
model=pfet_01v8
spiceprefix=X
}
C {madvlsi/pmos3.sym} 3150 -1820 3 0 {name=M20
L=0.15
W=1
body=VDD
nf=1
mult=1
ad="'int((nf+1)/2) * W/nf * 0.29'" 
pd="'2*int((nf+1)/2) * (W/nf + 0.29)'"
as="'int((nf+2)/2) * W/nf * 0.29'" 
ps="'2*int((nf+2)/2) * (W/nf + 0.29)'"
nrd="'0.29 / W'" nrs="'0.29 / W'"
sa=0 sb=0 sd=0
model=pfet_01v8
spiceprefix=X
}
C {madvlsi/pmos3.sym} 3230 -1820 3 0 {name=M21
L=0.15
W=1
body=VDD
nf=1
mult=1
ad="'int((nf+1)/2) * W/nf * 0.29'" 
pd="'2*int((nf+1)/2) * (W/nf + 0.29)'"
as="'int((nf+2)/2) * W/nf * 0.29'" 
ps="'2*int((nf+2)/2) * (W/nf + 0.29)'"
nrd="'0.29 / W'" nrs="'0.29 / W'"
sa=0 sb=0 sd=0
model=pfet_01v8
spiceprefix=X
}
C {madvlsi/vdd.sym} 3030 -1840 0 0 {name=l11 lab=VDD}
C {madvlsi/vdd.sym} 3190 -1840 0 0 {name=l12 lab=VDD}
C {madvlsi/nmos3.sym} 2990 -1650 3 0 {name=M22
L=0.15
W=1
body=GND
nf=1
mult=1
ad="'int((nf+1)/2) * W/nf * 0.29'" 
pd="'2*int((nf+1)/2) * (W/nf + 0.29)'"
as="'int((nf+2)/2) * W/nf * 0.29'" 
ps="'2*int((nf+2)/2) * (W/nf + 0.29)'"
nrd="'0.29 / W'" nrs="'0.29 / W'"
sa=0 sb=0 sd=0
model=nfet_01v8
spiceprefix=X
}
C {madvlsi/nmos3.sym} 3070 -1650 1 0 {name=M23
L=0.15
W=1
body=GND
nf=1
mult=1
ad="'int((nf+1)/2) * W/nf * 0.29'" 
pd="'2*int((nf+1)/2) * (W/nf + 0.29)'"
as="'int((nf+2)/2) * W/nf * 0.29'" 
ps="'2*int((nf+2)/2) * (W/nf + 0.29)'"
nrd="'0.29 / W'" nrs="'0.29 / W'"
sa=0 sb=0 sd=0
model=nfet_01v8
spiceprefix=X
}
C {madvlsi/nmos3.sym} 3150 -1650 1 0 {name=M24
L=0.15
W=1
body=GND
nf=1
mult=1
ad="'int((nf+1)/2) * W/nf * 0.29'" 
pd="'2*int((nf+1)/2) * (W/nf + 0.29)'"
as="'int((nf+2)/2) * W/nf * 0.29'" 
ps="'2*int((nf+2)/2) * (W/nf + 0.29)'"
nrd="'0.29 / W'" nrs="'0.29 / W'"
sa=0 sb=0 sd=0
model=nfet_01v8
spiceprefix=X
}
C {madvlsi/nmos3.sym} 3230 -1650 3 0 {name=M25
L=0.15
W=1
body=GND
nf=1
mult=1
ad="'int((nf+1)/2) * W/nf * 0.29'" 
pd="'2*int((nf+1)/2) * (W/nf + 0.29)'"
as="'int((nf+2)/2) * W/nf * 0.29'" 
ps="'2*int((nf+2)/2) * (W/nf + 0.29)'"
nrd="'0.29 / W'" nrs="'0.29 / W'"
sa=0 sb=0 sd=0
model=nfet_01v8
spiceprefix=X
}
C {madvlsi/gnd.sym} 3110 -1630 0 0 {name=l13 lab=GND}
C {madvlsi/nmos3.sym} 3320 -1650 1 0 {name=M26
L=0.15
W=1
body=GND
nf=1
mult=1
ad="'int((nf+1)/2) * W/nf * 0.29'" 
pd="'2*int((nf+1)/2) * (W/nf + 0.29)'"
as="'int((nf+2)/2) * W/nf * 0.29'" 
ps="'2*int((nf+2)/2) * (W/nf + 0.29)'"
nrd="'0.29 / W'" nrs="'0.29 / W'"
sa=0 sb=0 sd=0
model=nfet_01v8
spiceprefix=X
}
C {madvlsi/gnd.sym} 3350 -1630 0 0 {name=l14 lab=GND}
C {madvlsi/capacitor.sym} 2960 -1520 0 0 {name=C5
value=0.1p
m=1}
C {madvlsi/gnd.sym} 2960 -1490 0 0 {name=l15 lab=GND}
C {madvlsi/capacitor.sym} 3330 -1520 0 0 {name=C6
value=0.1p
m=1}
C {madvlsi/gnd.sym} 3330 -1490 0 0 {name=l18 lab=GND}
C {devices/lab_pin.sym} 2960 -1550 0 0 {name=p16 sig_type=std_logic lab=STO+b_RCL-b}
C {devices/lab_pin.sym} 3330 -1550 2 0 {name=p17 sig_type=std_logic lab=STO+_RCL-}
C {madvlsi/pmos3.sym} 980 -1130 3 1 {name=M27
L=0.15
W=1
body=VDD
nf=1
mult=1
ad="'int((nf+1)/2) * W/nf * 0.29'" 
pd="'2*int((nf+1)/2) * (W/nf + 0.29)'"
as="'int((nf+2)/2) * W/nf * 0.29'" 
ps="'2*int((nf+2)/2) * (W/nf + 0.29)'"
nrd="'0.29 / W'" nrs="'0.29 / W'"
sa=0 sb=0 sd=0
model=pfet_01v8
spiceprefix=X
}
C {madvlsi/pmos3.sym} 1080 -1130 3 1 {name=M28
L=0.15
W=1
body=VDD
nf=1
mult=1
ad="'int((nf+1)/2) * W/nf * 0.29'" 
pd="'2*int((nf+1)/2) * (W/nf + 0.29)'"
as="'int((nf+2)/2) * W/nf * 0.29'" 
ps="'2*int((nf+2)/2) * (W/nf + 0.29)'"
nrd="'0.29 / W'" nrs="'0.29 / W'"
sa=0 sb=0 sd=0
model=pfet_01v8
spiceprefix=X
}
C {madvlsi/pmos3.sym} 890 -1130 1 0 {name=M29
L=0.15
W=1
body=VDD
nf=1
mult=1
ad="'int((nf+1)/2) * W/nf * 0.29'" 
pd="'2*int((nf+1)/2) * (W/nf + 0.29)'"
as="'int((nf+2)/2) * W/nf * 0.29'" 
ps="'2*int((nf+2)/2) * (W/nf + 0.29)'"
nrd="'0.29 / W'" nrs="'0.29 / W'"
sa=0 sb=0 sd=0
model=pfet_01v8
spiceprefix=X
}
C {madvlsi/nmos3.sym} 730 -980 3 1 {name=M30
L=0.15
W=1
body=GND
nf=1
mult=1
ad="'int((nf+1)/2) * W/nf * 0.29'" 
pd="'2*int((nf+1)/2) * (W/nf + 0.29)'"
as="'int((nf+2)/2) * W/nf * 0.29'" 
ps="'2*int((nf+2)/2) * (W/nf + 0.29)'"
nrd="'0.29 / W'" nrs="'0.29 / W'"
sa=0 sb=0 sd=0
model=nfet_01v8
spiceprefix=X
}
C {madvlsi/nmos3.sym} 1130 -980 3 0 {name=M31
L=0.15
W=1
body=GND
nf=1
mult=1
ad="'int((nf+1)/2) * W/nf * 0.29'" 
pd="'2*int((nf+1)/2) * (W/nf + 0.29)'"
as="'int((nf+2)/2) * W/nf * 0.29'" 
ps="'2*int((nf+2)/2) * (W/nf + 0.29)'"
nrd="'0.29 / W'" nrs="'0.29 / W'"
sa=0 sb=0 sd=0
model=nfet_01v8
spiceprefix=X
}
C {madvlsi/nmos3.sym} 1030 -980 1 1 {name=M32
L=0.15
W=1
body=GND
nf=1
mult=1
ad="'int((nf+1)/2) * W/nf * 0.29'" 
pd="'2*int((nf+1)/2) * (W/nf + 0.29)'"
as="'int((nf+2)/2) * W/nf * 0.29'" 
ps="'2*int((nf+2)/2) * (W/nf + 0.29)'"
nrd="'0.29 / W'" nrs="'0.29 / W'"
sa=0 sb=0 sd=0
model=nfet_01v8
spiceprefix=X
}
C {devices/lab_pin.sym} 1030 -790 3 0 {name=p12 sig_type=std_logic lab=Db}
C {madvlsi/nmos3.sym} 1030 -820 1 1 {name=M33
L=0.15
W=1
body=GND
nf=1
mult=1
ad="'int((nf+1)/2) * W/nf * 0.29'" 
pd="'2*int((nf+1)/2) * (W/nf + 0.29)'"
as="'int((nf+2)/2) * W/nf * 0.29'" 
ps="'2*int((nf+2)/2) * (W/nf + 0.29)'"
nrd="'0.29 / W'" nrs="'0.29 / W'"
sa=0 sb=0 sd=0
model=nfet_01v8
spiceprefix=X
}
C {madvlsi/nmos3.sym} 970 -980 3 1 {name=M34
L=0.15
W=1
body=GND
nf=1
mult=1
ad="'int((nf+1)/2) * W/nf * 0.29'" 
pd="'2*int((nf+1)/2) * (W/nf + 0.29)'"
as="'int((nf+2)/2) * W/nf * 0.29'" 
ps="'2*int((nf+2)/2) * (W/nf + 0.29)'"
nrd="'0.29 / W'" nrs="'0.29 / W'"
sa=0 sb=0 sd=0
model=nfet_01v8
spiceprefix=X
}
C {madvlsi/nmos3.sym} 970 -820 3 1 {name=M35
L=0.15
W=1
body=GND
nf=1
mult=1
ad="'int((nf+1)/2) * W/nf * 0.29'" 
pd="'2*int((nf+1)/2) * (W/nf + 0.29)'"
as="'int((nf+2)/2) * W/nf * 0.29'" 
ps="'2*int((nf+2)/2) * (W/nf + 0.29)'"
nrd="'0.29 / W'" nrs="'0.29 / W'"
sa=0 sb=0 sd=0
model=nfet_01v8
spiceprefix=X
}
C {madvlsi/pmos3.sym} 1290 -1130 1 0 {name=M36
L=0.15
W=1
body=VDD
nf=1
mult=1
ad="'int((nf+1)/2) * W/nf * 0.29'" 
pd="'2*int((nf+1)/2) * (W/nf + 0.29)'"
as="'int((nf+2)/2) * W/nf * 0.29'" 
ps="'2*int((nf+2)/2) * (W/nf + 0.29)'"
nrd="'0.29 / W'" nrs="'0.29 / W'"
sa=0 sb=0 sd=0
model=pfet_01v8
spiceprefix=X
}
C {madvlsi/pmos3.sym} 1190 -1130 1 0 {name=M37
L=0.15
W=1
body=VDD
nf=1
mult=1
ad="'int((nf+1)/2) * W/nf * 0.29'" 
pd="'2*int((nf+1)/2) * (W/nf + 0.29)'"
as="'int((nf+2)/2) * W/nf * 0.29'" 
ps="'2*int((nf+2)/2) * (W/nf + 0.29)'"
nrd="'0.29 / W'" nrs="'0.29 / W'"
sa=0 sb=0 sd=0
model=pfet_01v8
spiceprefix=X
}
C {madvlsi/pmos3.sym} 1380 -1130 3 1 {name=M38
L=0.15
W=1
body=VDD
nf=1
mult=1
ad="'int((nf+1)/2) * W/nf * 0.29'" 
pd="'2*int((nf+1)/2) * (W/nf + 0.29)'"
as="'int((nf+2)/2) * W/nf * 0.29'" 
ps="'2*int((nf+2)/2) * (W/nf + 0.29)'"
nrd="'0.29 / W'" nrs="'0.29 / W'"
sa=0 sb=0 sd=0
model=pfet_01v8
spiceprefix=X
}
C {madvlsi/nmos3.sym} 1550 -980 1 0 {name=M39
L=0.15
W=1
body=GND
nf=1
mult=1
ad="'int((nf+1)/2) * W/nf * 0.29'" 
pd="'2*int((nf+1)/2) * (W/nf + 0.29)'"
as="'int((nf+2)/2) * W/nf * 0.29'" 
ps="'2*int((nf+2)/2) * (W/nf + 0.29)'"
nrd="'0.29 / W'" nrs="'0.29 / W'"
sa=0 sb=0 sd=0
model=nfet_01v8
spiceprefix=X
}
C {madvlsi/nmos3.sym} 1220 -980 3 0 {name=M40
L=0.15
W=1
body=GND
nf=1
mult=1
ad="'int((nf+1)/2) * W/nf * 0.29'" 
pd="'2*int((nf+1)/2) * (W/nf + 0.29)'"
as="'int((nf+2)/2) * W/nf * 0.29'" 
ps="'2*int((nf+2)/2) * (W/nf + 0.29)'"
nrd="'0.29 / W'" nrs="'0.29 / W'"
sa=0 sb=0 sd=0
model=nfet_01v8
spiceprefix=X
}
C {devices/lab_pin.sym} 1220 -790 1 1 {name=p14 sig_type=std_logic lab=D}
C {madvlsi/nmos3.sym} 1220 -820 3 0 {name=M41
L=0.15
W=1
body=GND
nf=1
mult=1
ad="'int((nf+1)/2) * W/nf * 0.29'" 
pd="'2*int((nf+1)/2) * (W/nf + 0.29)'"
as="'int((nf+2)/2) * W/nf * 0.29'" 
ps="'2*int((nf+2)/2) * (W/nf + 0.29)'"
nrd="'0.29 / W'" nrs="'0.29 / W'"
sa=0 sb=0 sd=0
model=nfet_01v8
spiceprefix=X
}
C {madvlsi/nmos3.sym} 1280 -980 1 0 {name=M42
L=0.15
W=1
body=GND
nf=1
mult=1
ad="'int((nf+1)/2) * W/nf * 0.29'" 
pd="'2*int((nf+1)/2) * (W/nf + 0.29)'"
as="'int((nf+2)/2) * W/nf * 0.29'" 
ps="'2*int((nf+2)/2) * (W/nf + 0.29)'"
nrd="'0.29 / W'" nrs="'0.29 / W'"
sa=0 sb=0 sd=0
model=nfet_01v8
spiceprefix=X
}
C {madvlsi/nmos3.sym} 1280 -820 1 0 {name=M43
L=0.15
W=1
body=GND
nf=1
mult=1
ad="'int((nf+1)/2) * W/nf * 0.29'" 
pd="'2*int((nf+1)/2) * (W/nf + 0.29)'"
as="'int((nf+2)/2) * W/nf * 0.29'" 
ps="'2*int((nf+2)/2) * (W/nf + 0.29)'"
nrd="'0.29 / W'" nrs="'0.29 / W'"
sa=0 sb=0 sd=0
model=nfet_01v8
spiceprefix=X
}
C {madvlsi/pmos3.sym} 730 -1130 3 1 {name=M44
L=0.15
W=1
body=VDD
nf=1
mult=1
ad="'int((nf+1)/2) * W/nf * 0.29'" 
pd="'2*int((nf+1)/2) * (W/nf + 0.29)'"
as="'int((nf+2)/2) * W/nf * 0.29'" 
ps="'2*int((nf+2)/2) * (W/nf + 0.29)'"
nrd="'0.29 / W'" nrs="'0.29 / W'"
sa=0 sb=0 sd=0
model=pfet_01v8
spiceprefix=X
}
C {madvlsi/pmos3.sym} 810 -1130 3 1 {name=M45
L=0.15
W=1
body=VDD
nf=1
mult=1
ad="'int((nf+1)/2) * W/nf * 0.29'" 
pd="'2*int((nf+1)/2) * (W/nf + 0.29)'"
as="'int((nf+2)/2) * W/nf * 0.29'" 
ps="'2*int((nf+2)/2) * (W/nf + 0.29)'"
nrd="'0.29 / W'" nrs="'0.29 / W'"
sa=0 sb=0 sd=0
model=pfet_01v8
spiceprefix=X
}
C {madvlsi/pmos3.sym} 1460 -1130 3 1 {name=M46
L=0.15
W=1
body=VDD
nf=1
mult=1
ad="'int((nf+1)/2) * W/nf * 0.29'" 
pd="'2*int((nf+1)/2) * (W/nf + 0.29)'"
as="'int((nf+2)/2) * W/nf * 0.29'" 
ps="'2*int((nf+2)/2) * (W/nf + 0.29)'"
nrd="'0.29 / W'" nrs="'0.29 / W'"
sa=0 sb=0 sd=0
model=pfet_01v8
spiceprefix=X
}
C {madvlsi/pmos3.sym} 1540 -1130 3 1 {name=M47
L=0.15
W=1
body=VDD
nf=1
mult=1
ad="'int((nf+1)/2) * W/nf * 0.29'" 
pd="'2*int((nf+1)/2) * (W/nf + 0.29)'"
as="'int((nf+2)/2) * W/nf * 0.29'" 
ps="'2*int((nf+2)/2) * (W/nf + 0.29)'"
nrd="'0.29 / W'" nrs="'0.29 / W'"
sa=0 sb=0 sd=0
model=pfet_01v8
spiceprefix=X
}
C {madvlsi/pmos3.sym} 640 -1130 1 0 {name=M48
L=0.15
W=1
body=VDD
nf=1
mult=1
ad="'int((nf+1)/2) * W/nf * 0.29'" 
pd="'2*int((nf+1)/2) * (W/nf + 0.29)'"
as="'int((nf+2)/2) * W/nf * 0.29'" 
ps="'2*int((nf+2)/2) * (W/nf + 0.29)'"
nrd="'0.29 / W'" nrs="'0.29 / W'"
sa=0 sb=0 sd=0
model=pfet_01v8
spiceprefix=X
}
C {madvlsi/nmos3.sym} 730 -820 3 0 {name=M49
L=0.15
W=1
body=GND
nf=1
mult=1
ad="'int((nf+1)/2) * W/nf * 0.29'" 
pd="'2*int((nf+1)/2) * (W/nf + 0.29)'"
as="'int((nf+2)/2) * W/nf * 0.29'" 
ps="'2*int((nf+2)/2) * (W/nf + 0.29)'"
nrd="'0.29 / W'" nrs="'0.29 / W'"
sa=0 sb=0 sd=0
model=nfet_01v8
spiceprefix=X
}
C {madvlsi/nmos3.sym} 810 -820 3 0 {name=M50
L=0.15
W=1
body=GND
nf=1
mult=1
ad="'int((nf+1)/2) * W/nf * 0.29'" 
pd="'2*int((nf+1)/2) * (W/nf + 0.29)'"
as="'int((nf+2)/2) * W/nf * 0.29'" 
ps="'2*int((nf+2)/2) * (W/nf + 0.29)'"
nrd="'0.29 / W'" nrs="'0.29 / W'"
sa=0 sb=0 sd=0
model=nfet_01v8
spiceprefix=X
}
C {madvlsi/nmos3.sym} 1460 -820 3 0 {name=M51
L=0.15
W=1
body=GND
nf=1
mult=1
ad="'int((nf+1)/2) * W/nf * 0.29'" 
pd="'2*int((nf+1)/2) * (W/nf + 0.29)'"
as="'int((nf+2)/2) * W/nf * 0.29'" 
ps="'2*int((nf+2)/2) * (W/nf + 0.29)'"
nrd="'0.29 / W'" nrs="'0.29 / W'"
sa=0 sb=0 sd=0
model=nfet_01v8
spiceprefix=X
}
C {madvlsi/nmos3.sym} 1540 -820 3 0 {name=M52
L=0.15
W=1
body=GND
nf=1
mult=1
ad="'int((nf+1)/2) * W/nf * 0.29'" 
pd="'2*int((nf+1)/2) * (W/nf + 0.29)'"
as="'int((nf+2)/2) * W/nf * 0.29'" 
ps="'2*int((nf+2)/2) * (W/nf + 0.29)'"
nrd="'0.29 / W'" nrs="'0.29 / W'"
sa=0 sb=0 sd=0
model=nfet_01v8
spiceprefix=X
}
C {madvlsi/pmos3.sym} 1630 -1130 1 0 {name=M53
L=0.15
W=1
body=VDD
nf=1
mult=1
ad="'int((nf+1)/2) * W/nf * 0.29'" 
pd="'2*int((nf+1)/2) * (W/nf + 0.29)'"
as="'int((nf+2)/2) * W/nf * 0.29'" 
ps="'2*int((nf+2)/2) * (W/nf + 0.29)'"
nrd="'0.29 / W'" nrs="'0.29 / W'"
sa=0 sb=0 sd=0
model=pfet_01v8
spiceprefix=X
}
C {madvlsi/nmos3.sym} 1630 -820 3 0 {name=M54
L=0.15
W=1
body=GND
nf=1
mult=1
ad="'int((nf+1)/2) * W/nf * 0.29'" 
pd="'2*int((nf+1)/2) * (W/nf + 0.29)'"
as="'int((nf+2)/2) * W/nf * 0.29'" 
ps="'2*int((nf+2)/2) * (W/nf + 0.29)'"
nrd="'0.29 / W'" nrs="'0.29 / W'"
sa=0 sb=0 sd=0
model=nfet_01v8
spiceprefix=X
}
C {madvlsi/nmos3.sym} 640 -820 3 0 {name=M55
L=0.15
W=1
body=GND
nf=1
mult=1
ad="'int((nf+1)/2) * W/nf * 0.29'" 
pd="'2*int((nf+1)/2) * (W/nf + 0.29)'"
as="'int((nf+2)/2) * W/nf * 0.29'" 
ps="'2*int((nf+2)/2) * (W/nf + 0.29)'"
nrd="'0.29 / W'" nrs="'0.29 / W'"
sa=0 sb=0 sd=0
model=nfet_01v8
spiceprefix=X
}
C {devices/lab_pin.sym} 150 -1130 0 0 {name=p30 sig_type=std_logic lab=Vref-}
C {madvlsi/capacitor.sym} 680 -790 0 0 {name=C3
value=1p
m=1}
C {madvlsi/capacitor.sym} 1740 -1010 0 0 {name=C4
value=1p
m=1}
C {madvlsi/pmos3.sym} 2540 -1140 3 1 {name=M56
L=0.15
W=1
body=VDD
nf=1
mult=1
ad="'int((nf+1)/2) * W/nf * 0.29'" 
pd="'2*int((nf+1)/2) * (W/nf + 0.29)'"
as="'int((nf+2)/2) * W/nf * 0.29'" 
ps="'2*int((nf+2)/2) * (W/nf + 0.29)'"
nrd="'0.29 / W'" nrs="'0.29 / W'"
sa=0 sb=0 sd=0
model=pfet_01v8
spiceprefix=X
}
C {madvlsi/pmos3.sym} 2640 -1140 3 1 {name=M57
L=0.15
W=1
body=VDD
nf=1
mult=1
ad="'int((nf+1)/2) * W/nf * 0.29'" 
pd="'2*int((nf+1)/2) * (W/nf + 0.29)'"
as="'int((nf+2)/2) * W/nf * 0.29'" 
ps="'2*int((nf+2)/2) * (W/nf + 0.29)'"
nrd="'0.29 / W'" nrs="'0.29 / W'"
sa=0 sb=0 sd=0
model=pfet_01v8
spiceprefix=X
}
C {madvlsi/pmos3.sym} 2450 -1140 1 0 {name=M58
L=0.15
W=1
body=VDD
nf=1
mult=1
ad="'int((nf+1)/2) * W/nf * 0.29'" 
pd="'2*int((nf+1)/2) * (W/nf + 0.29)'"
as="'int((nf+2)/2) * W/nf * 0.29'" 
ps="'2*int((nf+2)/2) * (W/nf + 0.29)'"
nrd="'0.29 / W'" nrs="'0.29 / W'"
sa=0 sb=0 sd=0
model=pfet_01v8
spiceprefix=X
}
C {madvlsi/nmos3.sym} 2290 -990 3 1 {name=M59
L=0.15
W=1
body=GND
nf=1
mult=1
ad="'int((nf+1)/2) * W/nf * 0.29'" 
pd="'2*int((nf+1)/2) * (W/nf + 0.29)'"
as="'int((nf+2)/2) * W/nf * 0.29'" 
ps="'2*int((nf+2)/2) * (W/nf + 0.29)'"
nrd="'0.29 / W'" nrs="'0.29 / W'"
sa=0 sb=0 sd=0
model=nfet_01v8
spiceprefix=X
}
C {madvlsi/nmos3.sym} 2690 -990 3 0 {name=M60
L=0.15
W=1
body=GND
nf=1
mult=1
ad="'int((nf+1)/2) * W/nf * 0.29'" 
pd="'2*int((nf+1)/2) * (W/nf + 0.29)'"
as="'int((nf+2)/2) * W/nf * 0.29'" 
ps="'2*int((nf+2)/2) * (W/nf + 0.29)'"
nrd="'0.29 / W'" nrs="'0.29 / W'"
sa=0 sb=0 sd=0
model=nfet_01v8
spiceprefix=X
}
C {madvlsi/nmos3.sym} 2590 -990 1 1 {name=M61
L=0.15
W=1
body=GND
nf=1
mult=1
ad="'int((nf+1)/2) * W/nf * 0.29'" 
pd="'2*int((nf+1)/2) * (W/nf + 0.29)'"
as="'int((nf+2)/2) * W/nf * 0.29'" 
ps="'2*int((nf+2)/2) * (W/nf + 0.29)'"
nrd="'0.29 / W'" nrs="'0.29 / W'"
sa=0 sb=0 sd=0
model=nfet_01v8
spiceprefix=X
}
C {devices/lab_pin.sym} 2590 -800 3 0 {name=p37 sig_type=std_logic lab=Db}
C {madvlsi/nmos3.sym} 2590 -830 1 1 {name=M62
L=0.15
W=1
body=GND
nf=1
mult=1
ad="'int((nf+1)/2) * W/nf * 0.29'" 
pd="'2*int((nf+1)/2) * (W/nf + 0.29)'"
as="'int((nf+2)/2) * W/nf * 0.29'" 
ps="'2*int((nf+2)/2) * (W/nf + 0.29)'"
nrd="'0.29 / W'" nrs="'0.29 / W'"
sa=0 sb=0 sd=0
model=nfet_01v8
spiceprefix=X
}
C {madvlsi/nmos3.sym} 2530 -990 3 1 {name=M63
L=0.15
W=1
body=GND
nf=1
mult=1
ad="'int((nf+1)/2) * W/nf * 0.29'" 
pd="'2*int((nf+1)/2) * (W/nf + 0.29)'"
as="'int((nf+2)/2) * W/nf * 0.29'" 
ps="'2*int((nf+2)/2) * (W/nf + 0.29)'"
nrd="'0.29 / W'" nrs="'0.29 / W'"
sa=0 sb=0 sd=0
model=nfet_01v8
spiceprefix=X
}
C {madvlsi/nmos3.sym} 2530 -830 3 1 {name=M64
L=0.15
W=1
body=GND
nf=1
mult=1
ad="'int((nf+1)/2) * W/nf * 0.29'" 
pd="'2*int((nf+1)/2) * (W/nf + 0.29)'"
as="'int((nf+2)/2) * W/nf * 0.29'" 
ps="'2*int((nf+2)/2) * (W/nf + 0.29)'"
nrd="'0.29 / W'" nrs="'0.29 / W'"
sa=0 sb=0 sd=0
model=nfet_01v8
spiceprefix=X
}
C {madvlsi/pmos3.sym} 2850 -1140 1 0 {name=M65
L=0.15
W=1
body=VDD
nf=1
mult=1
ad="'int((nf+1)/2) * W/nf * 0.29'" 
pd="'2*int((nf+1)/2) * (W/nf + 0.29)'"
as="'int((nf+2)/2) * W/nf * 0.29'" 
ps="'2*int((nf+2)/2) * (W/nf + 0.29)'"
nrd="'0.29 / W'" nrs="'0.29 / W'"
sa=0 sb=0 sd=0
model=pfet_01v8
spiceprefix=X
}
C {madvlsi/pmos3.sym} 2750 -1140 1 0 {name=M66
L=0.15
W=1
body=VDD
nf=1
mult=1
ad="'int((nf+1)/2) * W/nf * 0.29'" 
pd="'2*int((nf+1)/2) * (W/nf + 0.29)'"
as="'int((nf+2)/2) * W/nf * 0.29'" 
ps="'2*int((nf+2)/2) * (W/nf + 0.29)'"
nrd="'0.29 / W'" nrs="'0.29 / W'"
sa=0 sb=0 sd=0
model=pfet_01v8
spiceprefix=X
}
C {madvlsi/pmos3.sym} 2940 -1140 3 1 {name=M67
L=0.15
W=1
body=VDD
nf=1
mult=1
ad="'int((nf+1)/2) * W/nf * 0.29'" 
pd="'2*int((nf+1)/2) * (W/nf + 0.29)'"
as="'int((nf+2)/2) * W/nf * 0.29'" 
ps="'2*int((nf+2)/2) * (W/nf + 0.29)'"
nrd="'0.29 / W'" nrs="'0.29 / W'"
sa=0 sb=0 sd=0
model=pfet_01v8
spiceprefix=X
}
C {madvlsi/nmos3.sym} 3110 -990 1 0 {name=M68
L=0.15
W=1
body=GND
nf=1
mult=1
ad="'int((nf+1)/2) * W/nf * 0.29'" 
pd="'2*int((nf+1)/2) * (W/nf + 0.29)'"
as="'int((nf+2)/2) * W/nf * 0.29'" 
ps="'2*int((nf+2)/2) * (W/nf + 0.29)'"
nrd="'0.29 / W'" nrs="'0.29 / W'"
sa=0 sb=0 sd=0
model=nfet_01v8
spiceprefix=X
}
C {madvlsi/nmos3.sym} 2780 -990 3 0 {name=M69
L=0.15
W=1
body=GND
nf=1
mult=1
ad="'int((nf+1)/2) * W/nf * 0.29'" 
pd="'2*int((nf+1)/2) * (W/nf + 0.29)'"
as="'int((nf+2)/2) * W/nf * 0.29'" 
ps="'2*int((nf+2)/2) * (W/nf + 0.29)'"
nrd="'0.29 / W'" nrs="'0.29 / W'"
sa=0 sb=0 sd=0
model=nfet_01v8
spiceprefix=X
}
C {devices/lab_pin.sym} 2780 -800 1 1 {name=p38 sig_type=std_logic lab=D}
C {madvlsi/nmos3.sym} 2780 -830 3 0 {name=M70
L=0.15
W=1
body=GND
nf=1
mult=1
ad="'int((nf+1)/2) * W/nf * 0.29'" 
pd="'2*int((nf+1)/2) * (W/nf + 0.29)'"
as="'int((nf+2)/2) * W/nf * 0.29'" 
ps="'2*int((nf+2)/2) * (W/nf + 0.29)'"
nrd="'0.29 / W'" nrs="'0.29 / W'"
sa=0 sb=0 sd=0
model=nfet_01v8
spiceprefix=X
}
C {madvlsi/nmos3.sym} 2840 -990 1 0 {name=M71
L=0.15
W=1
body=GND
nf=1
mult=1
ad="'int((nf+1)/2) * W/nf * 0.29'" 
pd="'2*int((nf+1)/2) * (W/nf + 0.29)'"
as="'int((nf+2)/2) * W/nf * 0.29'" 
ps="'2*int((nf+2)/2) * (W/nf + 0.29)'"
nrd="'0.29 / W'" nrs="'0.29 / W'"
sa=0 sb=0 sd=0
model=nfet_01v8
spiceprefix=X
}
C {madvlsi/nmos3.sym} 2840 -830 1 0 {name=M72
L=0.15
W=1
body=GND
nf=1
mult=1
ad="'int((nf+1)/2) * W/nf * 0.29'" 
pd="'2*int((nf+1)/2) * (W/nf + 0.29)'"
as="'int((nf+2)/2) * W/nf * 0.29'" 
ps="'2*int((nf+2)/2) * (W/nf + 0.29)'"
nrd="'0.29 / W'" nrs="'0.29 / W'"
sa=0 sb=0 sd=0
model=nfet_01v8
spiceprefix=X
}
C {madvlsi/pmos3.sym} 2290 -1140 3 1 {name=M73
L=0.15
W=1
body=VDD
nf=1
mult=1
ad="'int((nf+1)/2) * W/nf * 0.29'" 
pd="'2*int((nf+1)/2) * (W/nf + 0.29)'"
as="'int((nf+2)/2) * W/nf * 0.29'" 
ps="'2*int((nf+2)/2) * (W/nf + 0.29)'"
nrd="'0.29 / W'" nrs="'0.29 / W'"
sa=0 sb=0 sd=0
model=pfet_01v8
spiceprefix=X
}
C {madvlsi/pmos3.sym} 2370 -1140 3 1 {name=M74
L=0.15
W=1
body=VDD
nf=1
mult=1
ad="'int((nf+1)/2) * W/nf * 0.29'" 
pd="'2*int((nf+1)/2) * (W/nf + 0.29)'"
as="'int((nf+2)/2) * W/nf * 0.29'" 
ps="'2*int((nf+2)/2) * (W/nf + 0.29)'"
nrd="'0.29 / W'" nrs="'0.29 / W'"
sa=0 sb=0 sd=0
model=pfet_01v8
spiceprefix=X
}
C {madvlsi/pmos3.sym} 3020 -1140 3 1 {name=M75
L=0.15
W=1
body=VDD
nf=1
mult=1
ad="'int((nf+1)/2) * W/nf * 0.29'" 
pd="'2*int((nf+1)/2) * (W/nf + 0.29)'"
as="'int((nf+2)/2) * W/nf * 0.29'" 
ps="'2*int((nf+2)/2) * (W/nf + 0.29)'"
nrd="'0.29 / W'" nrs="'0.29 / W'"
sa=0 sb=0 sd=0
model=pfet_01v8
spiceprefix=X
}
C {madvlsi/pmos3.sym} 3100 -1140 3 1 {name=M76
L=0.15
W=1
body=VDD
nf=1
mult=1
ad="'int((nf+1)/2) * W/nf * 0.29'" 
pd="'2*int((nf+1)/2) * (W/nf + 0.29)'"
as="'int((nf+2)/2) * W/nf * 0.29'" 
ps="'2*int((nf+2)/2) * (W/nf + 0.29)'"
nrd="'0.29 / W'" nrs="'0.29 / W'"
sa=0 sb=0 sd=0
model=pfet_01v8
spiceprefix=X
}
C {madvlsi/pmos3.sym} 2200 -1140 1 0 {name=M77
L=0.15
W=1
body=VDD
nf=1
mult=1
ad="'int((nf+1)/2) * W/nf * 0.29'" 
pd="'2*int((nf+1)/2) * (W/nf + 0.29)'"
as="'int((nf+2)/2) * W/nf * 0.29'" 
ps="'2*int((nf+2)/2) * (W/nf + 0.29)'"
nrd="'0.29 / W'" nrs="'0.29 / W'"
sa=0 sb=0 sd=0
model=pfet_01v8
spiceprefix=X
}
C {madvlsi/nmos3.sym} 2290 -830 3 0 {name=M78
L=0.15
W=1
body=GND
nf=1
mult=1
ad="'int((nf+1)/2) * W/nf * 0.29'" 
pd="'2*int((nf+1)/2) * (W/nf + 0.29)'"
as="'int((nf+2)/2) * W/nf * 0.29'" 
ps="'2*int((nf+2)/2) * (W/nf + 0.29)'"
nrd="'0.29 / W'" nrs="'0.29 / W'"
sa=0 sb=0 sd=0
model=nfet_01v8
spiceprefix=X
}
C {madvlsi/nmos3.sym} 2370 -830 3 0 {name=M79
L=0.15
W=1
body=GND
nf=1
mult=1
ad="'int((nf+1)/2) * W/nf * 0.29'" 
pd="'2*int((nf+1)/2) * (W/nf + 0.29)'"
as="'int((nf+2)/2) * W/nf * 0.29'" 
ps="'2*int((nf+2)/2) * (W/nf + 0.29)'"
nrd="'0.29 / W'" nrs="'0.29 / W'"
sa=0 sb=0 sd=0
model=nfet_01v8
spiceprefix=X
}
C {madvlsi/nmos3.sym} 3020 -830 3 0 {name=M80
L=0.15
W=1
body=GND
nf=1
mult=1
ad="'int((nf+1)/2) * W/nf * 0.29'" 
pd="'2*int((nf+1)/2) * (W/nf + 0.29)'"
as="'int((nf+2)/2) * W/nf * 0.29'" 
ps="'2*int((nf+2)/2) * (W/nf + 0.29)'"
nrd="'0.29 / W'" nrs="'0.29 / W'"
sa=0 sb=0 sd=0
model=nfet_01v8
spiceprefix=X
}
C {madvlsi/nmos3.sym} 3100 -830 3 0 {name=M81
L=0.15
W=1
body=GND
nf=1
mult=1
ad="'int((nf+1)/2) * W/nf * 0.29'" 
pd="'2*int((nf+1)/2) * (W/nf + 0.29)'"
as="'int((nf+2)/2) * W/nf * 0.29'" 
ps="'2*int((nf+2)/2) * (W/nf + 0.29)'"
nrd="'0.29 / W'" nrs="'0.29 / W'"
sa=0 sb=0 sd=0
model=nfet_01v8
spiceprefix=X
}
C {madvlsi/pmos3.sym} 3190 -1140 1 0 {name=M82
L=0.15
W=1
body=VDD
nf=1
mult=1
ad="'int((nf+1)/2) * W/nf * 0.29'" 
pd="'2*int((nf+1)/2) * (W/nf + 0.29)'"
as="'int((nf+2)/2) * W/nf * 0.29'" 
ps="'2*int((nf+2)/2) * (W/nf + 0.29)'"
nrd="'0.29 / W'" nrs="'0.29 / W'"
sa=0 sb=0 sd=0
model=pfet_01v8
spiceprefix=X
}
C {madvlsi/nmos3.sym} 3190 -830 3 0 {name=M83
L=0.15
W=1
body=GND
nf=1
mult=1
ad="'int((nf+1)/2) * W/nf * 0.29'" 
pd="'2*int((nf+1)/2) * (W/nf + 0.29)'"
as="'int((nf+2)/2) * W/nf * 0.29'" 
ps="'2*int((nf+2)/2) * (W/nf + 0.29)'"
nrd="'0.29 / W'" nrs="'0.29 / W'"
sa=0 sb=0 sd=0
model=nfet_01v8
spiceprefix=X
}
C {madvlsi/nmos3.sym} 2200 -830 3 0 {name=M84
L=0.15
W=1
body=GND
nf=1
mult=1
ad="'int((nf+1)/2) * W/nf * 0.29'" 
pd="'2*int((nf+1)/2) * (W/nf + 0.29)'"
as="'int((nf+2)/2) * W/nf * 0.29'" 
ps="'2*int((nf+2)/2) * (W/nf + 0.29)'"
nrd="'0.29 / W'" nrs="'0.29 / W'"
sa=0 sb=0 sd=0
model=nfet_01v8
spiceprefix=X
}
C {madvlsi/capacitor.sym} 2040 -1010 0 0 {name=C7
value=1p
m=1}
C {madvlsi/capacitor.sym} 3140 -800 0 0 {name=C8
value=1p
m=1}
C {devices/lab_pin.sym} 3690 -1140 2 0 {name=p57 sig_type=std_logic lab=Vref+}
C {madvlsi/nmos3.sym} 1910 -380 1 0 {name=M85
L=0.5
W=6
body=GND
nf=1
mult=1
ad="'int((nf+1)/2) * W/nf * 0.29'" 
pd="'2*int((nf+1)/2) * (W/nf + 0.29)'"
as="'int((nf+2)/2) * W/nf * 0.29'" 
ps="'2*int((nf+2)/2) * (W/nf + 0.29)'"
nrd="'0.29 / W'" nrs="'0.29 / W'"
sa=0 sb=0 sd=0
model=nfet_01v8
spiceprefix=X
}
C {madvlsi/nmos3.sym} 1990 -380 1 0 {name=M86
L=0.5
W=6
body=GND
nf=1
mult=1
ad="'int((nf+1)/2) * W/nf * 0.29'" 
pd="'2*int((nf+1)/2) * (W/nf + 0.29)'"
as="'int((nf+2)/2) * W/nf * 0.29'" 
ps="'2*int((nf+2)/2) * (W/nf + 0.29)'"
nrd="'0.29 / W'" nrs="'0.29 / W'"
sa=0 sb=0 sd=0
model=nfet_01v8
spiceprefix=X
}
C {madvlsi/nmos3.sym} 2070 -380 1 0 {name=M87
L=0.5
W=6
body=GND
nf=1
mult=1
ad="'int((nf+1)/2) * W/nf * 0.29'" 
pd="'2*int((nf+1)/2) * (W/nf + 0.29)'"
as="'int((nf+2)/2) * W/nf * 0.29'" 
ps="'2*int((nf+2)/2) * (W/nf + 0.29)'"
nrd="'0.29 / W'" nrs="'0.29 / W'"
sa=0 sb=0 sd=0
model=nfet_01v8
spiceprefix=X
}
C {madvlsi/nmos3.sym} 2150 -380 1 0 {name=M88
L=0.5
W=6
body=GND
nf=1
mult=1
ad="'int((nf+1)/2) * W/nf * 0.29'" 
pd="'2*int((nf+1)/2) * (W/nf + 0.29)'"
as="'int((nf+2)/2) * W/nf * 0.29'" 
ps="'2*int((nf+2)/2) * (W/nf + 0.29)'"
nrd="'0.29 / W'" nrs="'0.29 / W'"
sa=0 sb=0 sd=0
model=nfet_01v8
spiceprefix=X
}
C {madvlsi/nmos3.sym} 2230 -380 1 0 {name=M89
L=0.5
W=6
body=GND
nf=1
mult=1
ad="'int((nf+1)/2) * W/nf * 0.29'" 
pd="'2*int((nf+1)/2) * (W/nf + 0.29)'"
as="'int((nf+2)/2) * W/nf * 0.29'" 
ps="'2*int((nf+2)/2) * (W/nf + 0.29)'"
nrd="'0.29 / W'" nrs="'0.29 / W'"
sa=0 sb=0 sd=0
model=nfet_01v8
spiceprefix=X
}
C {madvlsi/nmos3.sym} 2310 -380 1 0 {name=M90
L=0.5
W=6
body=GND
nf=1
mult=1
ad="'int((nf+1)/2) * W/nf * 0.29'" 
pd="'2*int((nf+1)/2) * (W/nf + 0.29)'"
as="'int((nf+2)/2) * W/nf * 0.29'" 
ps="'2*int((nf+2)/2) * (W/nf + 0.29)'"
nrd="'0.29 / W'" nrs="'0.29 / W'"
sa=0 sb=0 sd=0
model=nfet_01v8
spiceprefix=X
}
C {madvlsi/nmos3.sym} 2390 -380 1 0 {name=M91
L=0.5
W=6
body=GND
nf=1
mult=1
ad="'int((nf+1)/2) * W/nf * 0.29'" 
pd="'2*int((nf+1)/2) * (W/nf + 0.29)'"
as="'int((nf+2)/2) * W/nf * 0.29'" 
ps="'2*int((nf+2)/2) * (W/nf + 0.29)'"
nrd="'0.29 / W'" nrs="'0.29 / W'"
sa=0 sb=0 sd=0
model=nfet_01v8
spiceprefix=X
}
C {madvlsi/nmos3.sym} 2470 -380 1 0 {name=M92
L=0.5
W=6
body=GND
nf=1
mult=1
ad="'int((nf+1)/2) * W/nf * 0.29'" 
pd="'2*int((nf+1)/2) * (W/nf + 0.29)'"
as="'int((nf+2)/2) * W/nf * 0.29'" 
ps="'2*int((nf+2)/2) * (W/nf + 0.29)'"
nrd="'0.29 / W'" nrs="'0.29 / W'"
sa=0 sb=0 sd=0
model=nfet_01v8
spiceprefix=X
}
C {madvlsi/nmos3.sym} 2550 -380 1 0 {name=M93
L=0.5
W=6
body=GND
nf=1
mult=1
ad="'int((nf+1)/2) * W/nf * 0.29'" 
pd="'2*int((nf+1)/2) * (W/nf + 0.29)'"
as="'int((nf+2)/2) * W/nf * 0.29'" 
ps="'2*int((nf+2)/2) * (W/nf + 0.29)'"
nrd="'0.29 / W'" nrs="'0.29 / W'"
sa=0 sb=0 sd=0
model=nfet_01v8
spiceprefix=X
}
C {madvlsi/nmos3.sym} 1190 -380 1 0 {name=M94
L=0.5
W=6
body=GND
nf=1
mult=1
ad="'int((nf+1)/2) * W/nf * 0.29'" 
pd="'2*int((nf+1)/2) * (W/nf + 0.29)'"
as="'int((nf+2)/2) * W/nf * 0.29'" 
ps="'2*int((nf+2)/2) * (W/nf + 0.29)'"
nrd="'0.29 / W'" nrs="'0.29 / W'"
sa=0 sb=0 sd=0
model=nfet_01v8
spiceprefix=X
}
C {madvlsi/nmos3.sym} 1270 -380 1 0 {name=M95
L=0.5
W=6
body=GND
nf=1
mult=1
ad="'int((nf+1)/2) * W/nf * 0.29'" 
pd="'2*int((nf+1)/2) * (W/nf + 0.29)'"
as="'int((nf+2)/2) * W/nf * 0.29'" 
ps="'2*int((nf+2)/2) * (W/nf + 0.29)'"
nrd="'0.29 / W'" nrs="'0.29 / W'"
sa=0 sb=0 sd=0
model=nfet_01v8
spiceprefix=X
}
C {madvlsi/nmos3.sym} 1350 -380 1 0 {name=M96
L=0.5
W=6
body=GND
nf=1
mult=1
ad="'int((nf+1)/2) * W/nf * 0.29'" 
pd="'2*int((nf+1)/2) * (W/nf + 0.29)'"
as="'int((nf+2)/2) * W/nf * 0.29'" 
ps="'2*int((nf+2)/2) * (W/nf + 0.29)'"
nrd="'0.29 / W'" nrs="'0.29 / W'"
sa=0 sb=0 sd=0
model=nfet_01v8
spiceprefix=X
}
C {madvlsi/nmos3.sym} 1430 -380 1 0 {name=M97
L=0.5
W=6
body=GND
nf=1
mult=1
ad="'int((nf+1)/2) * W/nf * 0.29'" 
pd="'2*int((nf+1)/2) * (W/nf + 0.29)'"
as="'int((nf+2)/2) * W/nf * 0.29'" 
ps="'2*int((nf+2)/2) * (W/nf + 0.29)'"
nrd="'0.29 / W'" nrs="'0.29 / W'"
sa=0 sb=0 sd=0
model=nfet_01v8
spiceprefix=X
}
C {madvlsi/nmos3.sym} 1510 -380 1 0 {name=M98
L=0.5
W=6
body=GND
nf=1
mult=1
ad="'int((nf+1)/2) * W/nf * 0.29'" 
pd="'2*int((nf+1)/2) * (W/nf + 0.29)'"
as="'int((nf+2)/2) * W/nf * 0.29'" 
ps="'2*int((nf+2)/2) * (W/nf + 0.29)'"
nrd="'0.29 / W'" nrs="'0.29 / W'"
sa=0 sb=0 sd=0
model=nfet_01v8
spiceprefix=X
}
C {madvlsi/nmos3.sym} 1590 -380 1 0 {name=M99
L=0.5
W=6
body=GND
nf=1
mult=1
ad="'int((nf+1)/2) * W/nf * 0.29'" 
pd="'2*int((nf+1)/2) * (W/nf + 0.29)'"
as="'int((nf+2)/2) * W/nf * 0.29'" 
ps="'2*int((nf+2)/2) * (W/nf + 0.29)'"
nrd="'0.29 / W'" nrs="'0.29 / W'"
sa=0 sb=0 sd=0
model=nfet_01v8
spiceprefix=X
}
C {madvlsi/nmos3.sym} 1670 -380 1 0 {name=M100
L=0.5
W=6
body=GND
nf=1
mult=1
ad="'int((nf+1)/2) * W/nf * 0.29'" 
pd="'2*int((nf+1)/2) * (W/nf + 0.29)'"
as="'int((nf+2)/2) * W/nf * 0.29'" 
ps="'2*int((nf+2)/2) * (W/nf + 0.29)'"
nrd="'0.29 / W'" nrs="'0.29 / W'"
sa=0 sb=0 sd=0
model=nfet_01v8
spiceprefix=X
}
C {madvlsi/nmos3.sym} 1750 -380 1 0 {name=M101
L=0.5
W=6
body=GND
nf=1
mult=1
ad="'int((nf+1)/2) * W/nf * 0.29'" 
pd="'2*int((nf+1)/2) * (W/nf + 0.29)'"
as="'int((nf+2)/2) * W/nf * 0.29'" 
ps="'2*int((nf+2)/2) * (W/nf + 0.29)'"
nrd="'0.29 / W'" nrs="'0.29 / W'"
sa=0 sb=0 sd=0
model=nfet_01v8
spiceprefix=X
}
C {madvlsi/nmos3.sym} 1830 -380 1 0 {name=M102
L=0.5
W=6
body=GND
nf=1
mult=1
ad="'int((nf+1)/2) * W/nf * 0.29'" 
pd="'2*int((nf+1)/2) * (W/nf + 0.29)'"
as="'int((nf+2)/2) * W/nf * 0.29'" 
ps="'2*int((nf+2)/2) * (W/nf + 0.29)'"
nrd="'0.29 / W'" nrs="'0.29 / W'"
sa=0 sb=0 sd=0
model=nfet_01v8
spiceprefix=X
}
C {madvlsi/gnd.sym} 1800 -300 0 0 {name=l3 lab=GND}
C {madvlsi/pmos3.sym} 2640 -380 3 0 {name=M103
L=0.5
W=6
body=VDD
nf=1
mult=1
ad="'int((nf+1)/2) * W/nf * 0.29'" 
pd="'2*int((nf+1)/2) * (W/nf + 0.29)'"
as="'int((nf+2)/2) * W/nf * 0.29'" 
ps="'2*int((nf+2)/2) * (W/nf + 0.29)'"
nrd="'0.29 / W'" nrs="'0.29 / W'"
sa=0 sb=0 sd=0
model=pfet_01v8
spiceprefix=X
}
C {madvlsi/pmos3.sym} 2720 -380 3 0 {name=M104
L=0.5
W=6
body=VDD
nf=1
mult=1
ad="'int((nf+1)/2) * W/nf * 0.29'" 
pd="'2*int((nf+1)/2) * (W/nf + 0.29)'"
as="'int((nf+2)/2) * W/nf * 0.29'" 
ps="'2*int((nf+2)/2) * (W/nf + 0.29)'"
nrd="'0.29 / W'" nrs="'0.29 / W'"
sa=0 sb=0 sd=0
model=pfet_01v8
spiceprefix=X
}
C {madvlsi/pmos3.sym} 1030 -380 3 0 {name=M105
L=0.5
W=6
body=VDD
nf=1
mult=1
ad="'int((nf+1)/2) * W/nf * 0.29'" 
pd="'2*int((nf+1)/2) * (W/nf + 0.29)'"
as="'int((nf+2)/2) * W/nf * 0.29'" 
ps="'2*int((nf+2)/2) * (W/nf + 0.29)'"
nrd="'0.29 / W'" nrs="'0.29 / W'"
sa=0 sb=0 sd=0
model=pfet_01v8
spiceprefix=X
}
C {madvlsi/pmos3.sym} 1110 -380 3 0 {name=M106
L=0.5
W=6
body=VDD
nf=1
mult=1
ad="'int((nf+1)/2) * W/nf * 0.29'" 
pd="'2*int((nf+1)/2) * (W/nf + 0.29)'"
as="'int((nf+2)/2) * W/nf * 0.29'" 
ps="'2*int((nf+2)/2) * (W/nf + 0.29)'"
nrd="'0.29 / W'" nrs="'0.29 / W'"
sa=0 sb=0 sd=0
model=pfet_01v8
spiceprefix=X
}
C {madvlsi/vdd.sym} 1070 -440 0 0 {name=l4 lab=VDD}
C {madvlsi/vdd.sym} 2680 -440 0 0 {name=l16 lab=VDD}
C {madvlsi/gnd.sym} 1940 -300 0 0 {name=l17 lab=GND}
C {madvlsi/nmos3.sym} 1910 -160 1 0 {name=M107
L=0.5
W=6
body=GND
nf=1
mult=1
ad="'int((nf+1)/2) * W/nf * 0.29'" 
pd="'2*int((nf+1)/2) * (W/nf + 0.29)'"
as="'int((nf+2)/2) * W/nf * 0.29'" 
ps="'2*int((nf+2)/2) * (W/nf + 0.29)'"
nrd="'0.29 / W'" nrs="'0.29 / W'"
sa=0 sb=0 sd=0
model=nfet_01v8
spiceprefix=X
}
C {madvlsi/nmos3.sym} 1990 -160 1 0 {name=M108
L=0.5
W=6
body=GND
nf=1
mult=1
ad="'int((nf+1)/2) * W/nf * 0.29'" 
pd="'2*int((nf+1)/2) * (W/nf + 0.29)'"
as="'int((nf+2)/2) * W/nf * 0.29'" 
ps="'2*int((nf+2)/2) * (W/nf + 0.29)'"
nrd="'0.29 / W'" nrs="'0.29 / W'"
sa=0 sb=0 sd=0
model=nfet_01v8
spiceprefix=X
}
C {madvlsi/nmos3.sym} 2070 -160 1 0 {name=M109
L=0.5
W=6
body=GND
nf=1
mult=1
ad="'int((nf+1)/2) * W/nf * 0.29'" 
pd="'2*int((nf+1)/2) * (W/nf + 0.29)'"
as="'int((nf+2)/2) * W/nf * 0.29'" 
ps="'2*int((nf+2)/2) * (W/nf + 0.29)'"
nrd="'0.29 / W'" nrs="'0.29 / W'"
sa=0 sb=0 sd=0
model=nfet_01v8
spiceprefix=X
}
C {madvlsi/nmos3.sym} 2150 -160 1 0 {name=M110
L=0.5
W=6
body=GND
nf=1
mult=1
ad="'int((nf+1)/2) * W/nf * 0.29'" 
pd="'2*int((nf+1)/2) * (W/nf + 0.29)'"
as="'int((nf+2)/2) * W/nf * 0.29'" 
ps="'2*int((nf+2)/2) * (W/nf + 0.29)'"
nrd="'0.29 / W'" nrs="'0.29 / W'"
sa=0 sb=0 sd=0
model=nfet_01v8
spiceprefix=X
}
C {madvlsi/nmos3.sym} 2230 -160 1 0 {name=M111
L=0.5
W=6
body=GND
nf=1
mult=1
ad="'int((nf+1)/2) * W/nf * 0.29'" 
pd="'2*int((nf+1)/2) * (W/nf + 0.29)'"
as="'int((nf+2)/2) * W/nf * 0.29'" 
ps="'2*int((nf+2)/2) * (W/nf + 0.29)'"
nrd="'0.29 / W'" nrs="'0.29 / W'"
sa=0 sb=0 sd=0
model=nfet_01v8
spiceprefix=X
}
C {madvlsi/nmos3.sym} 2310 -160 1 0 {name=M112
L=0.5
W=6
body=GND
nf=1
mult=1
ad="'int((nf+1)/2) * W/nf * 0.29'" 
pd="'2*int((nf+1)/2) * (W/nf + 0.29)'"
as="'int((nf+2)/2) * W/nf * 0.29'" 
ps="'2*int((nf+2)/2) * (W/nf + 0.29)'"
nrd="'0.29 / W'" nrs="'0.29 / W'"
sa=0 sb=0 sd=0
model=nfet_01v8
spiceprefix=X
}
C {madvlsi/nmos3.sym} 2390 -160 1 0 {name=M113
L=0.5
W=6
body=GND
nf=1
mult=1
ad="'int((nf+1)/2) * W/nf * 0.29'" 
pd="'2*int((nf+1)/2) * (W/nf + 0.29)'"
as="'int((nf+2)/2) * W/nf * 0.29'" 
ps="'2*int((nf+2)/2) * (W/nf + 0.29)'"
nrd="'0.29 / W'" nrs="'0.29 / W'"
sa=0 sb=0 sd=0
model=nfet_01v8
spiceprefix=X
}
C {madvlsi/nmos3.sym} 2470 -160 1 0 {name=M114
L=0.5
W=6
body=GND
nf=1
mult=1
ad="'int((nf+1)/2) * W/nf * 0.29'" 
pd="'2*int((nf+1)/2) * (W/nf + 0.29)'"
as="'int((nf+2)/2) * W/nf * 0.29'" 
ps="'2*int((nf+2)/2) * (W/nf + 0.29)'"
nrd="'0.29 / W'" nrs="'0.29 / W'"
sa=0 sb=0 sd=0
model=nfet_01v8
spiceprefix=X
}
C {madvlsi/nmos3.sym} 2550 -160 1 0 {name=M115
L=0.5
W=6
body=GND
nf=1
mult=1
ad="'int((nf+1)/2) * W/nf * 0.29'" 
pd="'2*int((nf+1)/2) * (W/nf + 0.29)'"
as="'int((nf+2)/2) * W/nf * 0.29'" 
ps="'2*int((nf+2)/2) * (W/nf + 0.29)'"
nrd="'0.29 / W'" nrs="'0.29 / W'"
sa=0 sb=0 sd=0
model=nfet_01v8
spiceprefix=X
}
C {madvlsi/nmos3.sym} 1190 -160 1 0 {name=M116
L=0.5
W=6
body=GND
nf=1
mult=1
ad="'int((nf+1)/2) * W/nf * 0.29'" 
pd="'2*int((nf+1)/2) * (W/nf + 0.29)'"
as="'int((nf+2)/2) * W/nf * 0.29'" 
ps="'2*int((nf+2)/2) * (W/nf + 0.29)'"
nrd="'0.29 / W'" nrs="'0.29 / W'"
sa=0 sb=0 sd=0
model=nfet_01v8
spiceprefix=X
}
C {madvlsi/nmos3.sym} 1270 -160 1 0 {name=M117
L=0.5
W=6
body=GND
nf=1
mult=1
ad="'int((nf+1)/2) * W/nf * 0.29'" 
pd="'2*int((nf+1)/2) * (W/nf + 0.29)'"
as="'int((nf+2)/2) * W/nf * 0.29'" 
ps="'2*int((nf+2)/2) * (W/nf + 0.29)'"
nrd="'0.29 / W'" nrs="'0.29 / W'"
sa=0 sb=0 sd=0
model=nfet_01v8
spiceprefix=X
}
C {madvlsi/nmos3.sym} 1350 -160 1 0 {name=M118
L=0.5
W=6
body=GND
nf=1
mult=1
ad="'int((nf+1)/2) * W/nf * 0.29'" 
pd="'2*int((nf+1)/2) * (W/nf + 0.29)'"
as="'int((nf+2)/2) * W/nf * 0.29'" 
ps="'2*int((nf+2)/2) * (W/nf + 0.29)'"
nrd="'0.29 / W'" nrs="'0.29 / W'"
sa=0 sb=0 sd=0
model=nfet_01v8
spiceprefix=X
}
C {madvlsi/nmos3.sym} 1430 -160 1 0 {name=M119
L=0.5
W=6
body=GND
nf=1
mult=1
ad="'int((nf+1)/2) * W/nf * 0.29'" 
pd="'2*int((nf+1)/2) * (W/nf + 0.29)'"
as="'int((nf+2)/2) * W/nf * 0.29'" 
ps="'2*int((nf+2)/2) * (W/nf + 0.29)'"
nrd="'0.29 / W'" nrs="'0.29 / W'"
sa=0 sb=0 sd=0
model=nfet_01v8
spiceprefix=X
}
C {madvlsi/nmos3.sym} 1510 -160 1 0 {name=M120
L=0.5
W=6
body=GND
nf=1
mult=1
ad="'int((nf+1)/2) * W/nf * 0.29'" 
pd="'2*int((nf+1)/2) * (W/nf + 0.29)'"
as="'int((nf+2)/2) * W/nf * 0.29'" 
ps="'2*int((nf+2)/2) * (W/nf + 0.29)'"
nrd="'0.29 / W'" nrs="'0.29 / W'"
sa=0 sb=0 sd=0
model=nfet_01v8
spiceprefix=X
}
C {madvlsi/nmos3.sym} 1590 -160 1 0 {name=M121
L=0.5
W=6
body=GND
nf=1
mult=1
ad="'int((nf+1)/2) * W/nf * 0.29'" 
pd="'2*int((nf+1)/2) * (W/nf + 0.29)'"
as="'int((nf+2)/2) * W/nf * 0.29'" 
ps="'2*int((nf+2)/2) * (W/nf + 0.29)'"
nrd="'0.29 / W'" nrs="'0.29 / W'"
sa=0 sb=0 sd=0
model=nfet_01v8
spiceprefix=X
}
C {madvlsi/nmos3.sym} 1670 -160 1 0 {name=M122
L=0.5
W=6
body=GND
nf=1
mult=1
ad="'int((nf+1)/2) * W/nf * 0.29'" 
pd="'2*int((nf+1)/2) * (W/nf + 0.29)'"
as="'int((nf+2)/2) * W/nf * 0.29'" 
ps="'2*int((nf+2)/2) * (W/nf + 0.29)'"
nrd="'0.29 / W'" nrs="'0.29 / W'"
sa=0 sb=0 sd=0
model=nfet_01v8
spiceprefix=X
}
C {madvlsi/nmos3.sym} 1750 -160 1 0 {name=M123
L=0.5
W=6
body=GND
nf=1
mult=1
ad="'int((nf+1)/2) * W/nf * 0.29'" 
pd="'2*int((nf+1)/2) * (W/nf + 0.29)'"
as="'int((nf+2)/2) * W/nf * 0.29'" 
ps="'2*int((nf+2)/2) * (W/nf + 0.29)'"
nrd="'0.29 / W'" nrs="'0.29 / W'"
sa=0 sb=0 sd=0
model=nfet_01v8
spiceprefix=X
}
C {madvlsi/nmos3.sym} 1830 -160 1 0 {name=M124
L=0.5
W=6
body=GND
nf=1
mult=1
ad="'int((nf+1)/2) * W/nf * 0.29'" 
pd="'2*int((nf+1)/2) * (W/nf + 0.29)'"
as="'int((nf+2)/2) * W/nf * 0.29'" 
ps="'2*int((nf+2)/2) * (W/nf + 0.29)'"
nrd="'0.29 / W'" nrs="'0.29 / W'"
sa=0 sb=0 sd=0
model=nfet_01v8
spiceprefix=X
}
C {madvlsi/gnd.sym} 1800 -80 0 0 {name=l20 lab=GND}
C {madvlsi/pmos3.sym} 2640 -160 3 0 {name=M125
L=0.5
W=6
body=VDD
nf=1
mult=1
ad="'int((nf+1)/2) * W/nf * 0.29'" 
pd="'2*int((nf+1)/2) * (W/nf + 0.29)'"
as="'int((nf+2)/2) * W/nf * 0.29'" 
ps="'2*int((nf+2)/2) * (W/nf + 0.29)'"
nrd="'0.29 / W'" nrs="'0.29 / W'"
sa=0 sb=0 sd=0
model=pfet_01v8
spiceprefix=X
}
C {madvlsi/pmos3.sym} 2720 -160 3 0 {name=M126
L=0.5
W=6
body=VDD
nf=1
mult=1
ad="'int((nf+1)/2) * W/nf * 0.29'" 
pd="'2*int((nf+1)/2) * (W/nf + 0.29)'"
as="'int((nf+2)/2) * W/nf * 0.29'" 
ps="'2*int((nf+2)/2) * (W/nf + 0.29)'"
nrd="'0.29 / W'" nrs="'0.29 / W'"
sa=0 sb=0 sd=0
model=pfet_01v8
spiceprefix=X
}
C {madvlsi/pmos3.sym} 1030 -160 3 0 {name=M127
L=0.5
W=6
body=VDD
nf=1
mult=1
ad="'int((nf+1)/2) * W/nf * 0.29'" 
pd="'2*int((nf+1)/2) * (W/nf + 0.29)'"
as="'int((nf+2)/2) * W/nf * 0.29'" 
ps="'2*int((nf+2)/2) * (W/nf + 0.29)'"
nrd="'0.29 / W'" nrs="'0.29 / W'"
sa=0 sb=0 sd=0
model=pfet_01v8
spiceprefix=X
}
C {madvlsi/pmos3.sym} 1110 -160 3 0 {name=M128
L=0.5
W=6
body=VDD
nf=1
mult=1
ad="'int((nf+1)/2) * W/nf * 0.29'" 
pd="'2*int((nf+1)/2) * (W/nf + 0.29)'"
as="'int((nf+2)/2) * W/nf * 0.29'" 
ps="'2*int((nf+2)/2) * (W/nf + 0.29)'"
nrd="'0.29 / W'" nrs="'0.29 / W'"
sa=0 sb=0 sd=0
model=pfet_01v8
spiceprefix=X
}
C {madvlsi/vdd.sym} 1070 -220 0 0 {name=l21 lab=VDD}
C {madvlsi/vdd.sym} 2680 -220 0 0 {name=l22 lab=VDD}
C {madvlsi/gnd.sym} 1940 -80 0 0 {name=l23 lab=GND}
C {madvlsi/vdd.sym} 1030 -1130 0 0 {name=l25 lab=VDD}
C {madvlsi/gnd.sym} 2720 -960 0 0 {name=l28 lab=GND}
C {madvlsi/gnd.sym} 2040 -980 0 0 {name=l29 lab=GND}
C {madvlsi/gnd.sym} 3140 -770 0 0 {name=l30 lab=GND}
C {madvlsi/gnd.sym} 1740 -980 0 0 {name=l31 lab=GND}
C {madvlsi/gnd.sym} 680 -760 0 0 {name=l32 lab=GND}
C {devices/lab_pin.sym} 1140 -560 0 0 {name=p7 sig_type=std_logic lab=Vb}
C {devices/lab_pin.sym} 890 -370 0 0 {name=p31 sig_type=std_logic lab=Vcp}
C {madvlsi/pmos3.sym} 1880 -1130 1 0 {name=M149
L=0.15
W=1
body=VDD
nf=1
mult=1
ad="'int((nf+1)/2) * W/nf * 0.29'" 
pd="'2*int((nf+1)/2) * (W/nf + 0.29)'"
as="'int((nf+2)/2) * W/nf * 0.29'" 
ps="'2*int((nf+2)/2) * (W/nf + 0.29)'"
nrd="'0.29 / W'" nrs="'0.29 / W'"
sa=0 sb=0 sd=0
model=pfet_01v8
spiceprefix=X
}
C {madvlsi/nmos3.sym} 1880 -810 3 0 {name=M150
L=0.15
W=1
body=GND
nf=1
mult=1
ad="'int((nf+1)/2) * W/nf * 0.29'" 
pd="'2*int((nf+1)/2) * (W/nf + 0.29)'"
as="'int((nf+2)/2) * W/nf * 0.29'" 
ps="'2*int((nf+2)/2) * (W/nf + 0.29)'"
nrd="'0.29 / W'" nrs="'0.29 / W'"
sa=0 sb=0 sd=0
model=nfet_01v8
spiceprefix=X
}
C {devices/lab_pin.sym} 1880 -780 3 0 {name=p35 sig_type=std_logic lab=SH}
C {devices/lab_pin.sym} 1880 -1160 1 0 {name=p58 sig_type=std_logic lab=SHb}
C {devices/lab_pin.sym} 1740 -1040 1 0 {name=p52 sig_type=std_logic lab=C-}
C {devices/lab_pin.sym} 2040 -1040 1 0 {name=p55 sig_type=std_logic lab=C+}
C {madvlsi/pmos3.sym} 950 -1890 1 1 {name=M129
L=0.15
W=1
body=VDD
nf=1
mult=1
ad="'int((nf+1)/2) * W/nf * 0.29'" 
pd="'2*int((nf+1)/2) * (W/nf + 0.29)'"
as="'int((nf+2)/2) * W/nf * 0.29'" 
ps="'2*int((nf+2)/2) * (W/nf + 0.29)'"
nrd="'0.29 / W'" nrs="'0.29 / W'"
sa=0 sb=0 sd=0
model=pfet_01v8
spiceprefix=X
}
C {madvlsi/pmos3.sym} 1030 -1890 3 1 {name=M130
L=0.15
W=1
body=VDD
nf=1
mult=1
ad="'int((nf+1)/2) * W/nf * 0.29'" 
pd="'2*int((nf+1)/2) * (W/nf + 0.29)'"
as="'int((nf+2)/2) * W/nf * 0.29'" 
ps="'2*int((nf+2)/2) * (W/nf + 0.29)'"
nrd="'0.29 / W'" nrs="'0.29 / W'"
sa=0 sb=0 sd=0
model=pfet_01v8
spiceprefix=X
}
C {madvlsi/pmos3.sym} 1110 -1890 3 1 {name=M131
L=0.15
W=1
body=VDD
nf=1
mult=1
ad="'int((nf+1)/2) * W/nf * 0.29'" 
pd="'2*int((nf+1)/2) * (W/nf + 0.29)'"
as="'int((nf+2)/2) * W/nf * 0.29'" 
ps="'2*int((nf+2)/2) * (W/nf + 0.29)'"
nrd="'0.29 / W'" nrs="'0.29 / W'"
sa=0 sb=0 sd=0
model=pfet_01v8
spiceprefix=X
}
C {madvlsi/pmos3.sym} 1190 -1890 3 1 {name=M132
L=0.15
W=1
body=VDD
nf=1
mult=1
ad="'int((nf+1)/2) * W/nf * 0.29'" 
pd="'2*int((nf+1)/2) * (W/nf + 0.29)'"
as="'int((nf+2)/2) * W/nf * 0.29'" 
ps="'2*int((nf+2)/2) * (W/nf + 0.29)'"
nrd="'0.29 / W'" nrs="'0.29 / W'"
sa=0 sb=0 sd=0
model=pfet_01v8
spiceprefix=X
}
C {madvlsi/pmos3.sym} 1270 -1890 3 1 {name=M133
L=0.15
W=1
body=VDD
nf=1
mult=1
ad="'int((nf+1)/2) * W/nf * 0.29'" 
pd="'2*int((nf+1)/2) * (W/nf + 0.29)'"
as="'int((nf+2)/2) * W/nf * 0.29'" 
ps="'2*int((nf+2)/2) * (W/nf + 0.29)'"
nrd="'0.29 / W'" nrs="'0.29 / W'"
sa=0 sb=0 sd=0
model=pfet_01v8
spiceprefix=X
}
C {madvlsi/pmos3.sym} 1350 -1890 1 1 {name=M134
L=0.15
W=1
body=VDD
nf=1
mult=1
ad="'int((nf+1)/2) * W/nf * 0.29'" 
pd="'2*int((nf+1)/2) * (W/nf + 0.29)'"
as="'int((nf+2)/2) * W/nf * 0.29'" 
ps="'2*int((nf+2)/2) * (W/nf + 0.29)'"
nrd="'0.29 / W'" nrs="'0.29 / W'"
sa=0 sb=0 sd=0
model=pfet_01v8
spiceprefix=X
}
C {madvlsi/pmos3.sym} 1430 -1890 1 1 {name=M135
L=0.15
W=1
body=VDD
nf=1
mult=1
ad="'int((nf+1)/2) * W/nf * 0.29'" 
pd="'2*int((nf+1)/2) * (W/nf + 0.29)'"
as="'int((nf+2)/2) * W/nf * 0.29'" 
ps="'2*int((nf+2)/2) * (W/nf + 0.29)'"
nrd="'0.29 / W'" nrs="'0.29 / W'"
sa=0 sb=0 sd=0
model=pfet_01v8
spiceprefix=X
}
C {madvlsi/vdd.sym} 1070 -1940 0 0 {name=l26 lab=VDD}
C {madvlsi/vdd.sym} 1230 -1940 0 0 {name=l34 lab=VDD}
C {madvlsi/nmos3.sym} 950 -1740 1 0 {name=M136
L=0.15
W=1
body=GND
nf=1
mult=1
ad="'int((nf+1)/2) * W/nf * 0.29'" 
pd="'2*int((nf+1)/2) * (W/nf + 0.29)'"
as="'int((nf+2)/2) * W/nf * 0.29'" 
ps="'2*int((nf+2)/2) * (W/nf + 0.29)'"
nrd="'0.29 / W'" nrs="'0.29 / W'"
sa=0 sb=0 sd=0
model=nfet_01v8
spiceprefix=X
}
C {madvlsi/nmos3.sym} 1030 -1740 1 0 {name=M137
L=0.15
W=1
body=GND
nf=1
mult=1
ad="'int((nf+1)/2) * W/nf * 0.29'" 
pd="'2*int((nf+1)/2) * (W/nf + 0.29)'"
as="'int((nf+2)/2) * W/nf * 0.29'" 
ps="'2*int((nf+2)/2) * (W/nf + 0.29)'"
nrd="'0.29 / W'" nrs="'0.29 / W'"
sa=0 sb=0 sd=0
model=nfet_01v8
spiceprefix=X
}
C {madvlsi/nmos3.sym} 1110 -1740 3 0 {name=M138
L=0.15
W=1
body=GND
nf=1
mult=1
ad="'int((nf+1)/2) * W/nf * 0.29'" 
pd="'2*int((nf+1)/2) * (W/nf + 0.29)'"
as="'int((nf+2)/2) * W/nf * 0.29'" 
ps="'2*int((nf+2)/2) * (W/nf + 0.29)'"
nrd="'0.29 / W'" nrs="'0.29 / W'"
sa=0 sb=0 sd=0
model=nfet_01v8
spiceprefix=X
}
C {madvlsi/nmos3.sym} 1190 -1740 3 0 {name=M139
L=0.15
W=1
body=GND
nf=1
mult=1
ad="'int((nf+1)/2) * W/nf * 0.29'" 
pd="'2*int((nf+1)/2) * (W/nf + 0.29)'"
as="'int((nf+2)/2) * W/nf * 0.29'" 
ps="'2*int((nf+2)/2) * (W/nf + 0.29)'"
nrd="'0.29 / W'" nrs="'0.29 / W'"
sa=0 sb=0 sd=0
model=nfet_01v8
spiceprefix=X
}
C {madvlsi/nmos3.sym} 1270 -1740 1 0 {name=M140
L=0.15
W=1
body=GND
nf=1
mult=1
ad="'int((nf+1)/2) * W/nf * 0.29'" 
pd="'2*int((nf+1)/2) * (W/nf + 0.29)'"
as="'int((nf+2)/2) * W/nf * 0.29'" 
ps="'2*int((nf+2)/2) * (W/nf + 0.29)'"
nrd="'0.29 / W'" nrs="'0.29 / W'"
sa=0 sb=0 sd=0
model=nfet_01v8
spiceprefix=X
}
C {madvlsi/nmos3.sym} 1350 -1740 3 0 {name=M141
L=0.15
W=1
body=GND
nf=1
mult=1
ad="'int((nf+1)/2) * W/nf * 0.29'" 
pd="'2*int((nf+1)/2) * (W/nf + 0.29)'"
as="'int((nf+2)/2) * W/nf * 0.29'" 
ps="'2*int((nf+2)/2) * (W/nf + 0.29)'"
nrd="'0.29 / W'" nrs="'0.29 / W'"
sa=0 sb=0 sd=0
model=nfet_01v8
spiceprefix=X
}
C {madvlsi/nmos3.sym} 950 -1560 1 0 {name=M142
L=0.15
W=1
body=GND
nf=1
mult=1
ad="'int((nf+1)/2) * W/nf * 0.29'" 
pd="'2*int((nf+1)/2) * (W/nf + 0.29)'"
as="'int((nf+2)/2) * W/nf * 0.29'" 
ps="'2*int((nf+2)/2) * (W/nf + 0.29)'"
nrd="'0.29 / W'" nrs="'0.29 / W'"
sa=0 sb=0 sd=0
model=nfet_01v8
spiceprefix=X
}
C {madvlsi/nmos3.sym} 1030 -1560 1 0 {name=M143
L=0.15
W=1
body=GND
nf=1
mult=1
ad="'int((nf+1)/2) * W/nf * 0.29'" 
pd="'2*int((nf+1)/2) * (W/nf + 0.29)'"
as="'int((nf+2)/2) * W/nf * 0.29'" 
ps="'2*int((nf+2)/2) * (W/nf + 0.29)'"
nrd="'0.29 / W'" nrs="'0.29 / W'"
sa=0 sb=0 sd=0
model=nfet_01v8
spiceprefix=X
}
C {madvlsi/nmos3.sym} 1110 -1560 1 0 {name=M144
L=0.15
W=1
body=GND
nf=1
mult=1
ad="'int((nf+1)/2) * W/nf * 0.29'" 
pd="'2*int((nf+1)/2) * (W/nf + 0.29)'"
as="'int((nf+2)/2) * W/nf * 0.29'" 
ps="'2*int((nf+2)/2) * (W/nf + 0.29)'"
nrd="'0.29 / W'" nrs="'0.29 / W'"
sa=0 sb=0 sd=0
model=nfet_01v8
spiceprefix=X
}
C {madvlsi/nmos3.sym} 1190 -1560 1 0 {name=M145
L=0.15
W=1
body=GND
nf=1
mult=1
ad="'int((nf+1)/2) * W/nf * 0.29'" 
pd="'2*int((nf+1)/2) * (W/nf + 0.29)'"
as="'int((nf+2)/2) * W/nf * 0.29'" 
ps="'2*int((nf+2)/2) * (W/nf + 0.29)'"
nrd="'0.29 / W'" nrs="'0.29 / W'"
sa=0 sb=0 sd=0
model=nfet_01v8
spiceprefix=X
}
C {madvlsi/nmos3.sym} 1270 -1560 3 0 {name=M146
L=0.15
W=1
body=GND
nf=1
mult=1
ad="'int((nf+1)/2) * W/nf * 0.29'" 
pd="'2*int((nf+1)/2) * (W/nf + 0.29)'"
as="'int((nf+2)/2) * W/nf * 0.29'" 
ps="'2*int((nf+2)/2) * (W/nf + 0.29)'"
nrd="'0.29 / W'" nrs="'0.29 / W'"
sa=0 sb=0 sd=0
model=nfet_01v8
spiceprefix=X
}
C {madvlsi/nmos3.sym} 1350 -1560 1 0 {name=M147
L=0.15
W=1
body=GND
nf=1
mult=1
ad="'int((nf+1)/2) * W/nf * 0.29'" 
pd="'2*int((nf+1)/2) * (W/nf + 0.29)'"
as="'int((nf+2)/2) * W/nf * 0.29'" 
ps="'2*int((nf+2)/2) * (W/nf + 0.29)'"
nrd="'0.29 / W'" nrs="'0.29 / W'"
sa=0 sb=0 sd=0
model=nfet_01v8
spiceprefix=X
}
C {madvlsi/nmos3.sym} 1430 -1560 1 0 {name=M148
L=0.15
W=1
body=GND
nf=1
mult=1
ad="'int((nf+1)/2) * W/nf * 0.29'" 
pd="'2*int((nf+1)/2) * (W/nf + 0.29)'"
as="'int((nf+2)/2) * W/nf * 0.29'" 
ps="'2*int((nf+2)/2) * (W/nf + 0.29)'"
nrd="'0.29 / W'" nrs="'0.29 / W'"
sa=0 sb=0 sd=0
model=nfet_01v8
spiceprefix=X
}
C {madvlsi/vdd.sym} 1400 -1940 0 0 {name=l35 lab=VDD}
C {devices/lab_pin.sym} 560 -1590 0 0 {name=p60 sig_type=std_logic lab=RST}
C {madvlsi/capacitor.sym} 990 -1460 0 0 {name=C9
value=0.1p
m=1}
C {madvlsi/gnd.sym} 990 -1430 0 0 {name=l36 lab=GND}
C {madvlsi/capacitor.sym} 1070 -1460 0 0 {name=C10
value=0.1p
m=1}
C {madvlsi/gnd.sym} 1070 -1430 0 0 {name=l37 lab=GND}
C {madvlsi/gnd.sym} 1230 -1550 0 0 {name=l38 lab=GND}
C {devices/lab_pin.sym} 1740 -1980 1 0 {name=p62 sig_type=std_logic lab=CompOut}
C {madvlsi/gnd.sym} 990 -1730 0 0 {name=l39 lab=GND}
C {madvlsi/gnd.sym} 1300 -1730 0 0 {name=l40 lab=GND}
C {devices/lab_pin.sym} 560 -1670 0 0 {name=p63 sig_type=std_logic lab=AIn}
C {devices/lab_pin.sym} 1380 -1820 0 0 {name=p69 sig_type=std_logic lab=CompOutb}
C {madvlsi/pmos3.sym} 490 -1030 2 1 {name=M151
L=0.15
W=1
body=VDD
nf=1
mult=1
ad="'int((nf+1)/2) * W/nf * 0.29'" 
pd="'2*int((nf+1)/2) * (W/nf + 0.29)'"
as="'int((nf+2)/2) * W/nf * 0.29'" 
ps="'2*int((nf+2)/2) * (W/nf + 0.29)'"
nrd="'0.29 / W'" nrs="'0.29 / W'"
sa=0 sb=0 sd=0
model=pfet_01v8
spiceprefix=X
}
C {madvlsi/nmos3.sym} 490 -930 0 0 {name=M152
L=0.15
W=1
body=GND
nf=1
mult=1
ad="'int((nf+1)/2) * W/nf * 0.29'" 
pd="'2*int((nf+1)/2) * (W/nf + 0.29)'"
as="'int((nf+2)/2) * W/nf * 0.29'" 
ps="'2*int((nf+2)/2) * (W/nf + 0.29)'"
nrd="'0.29 / W'" nrs="'0.29 / W'"
sa=0 sb=0 sd=0
model=nfet_01v8
spiceprefix=X
}
C {madvlsi/vdd.sym} 490 -1060 0 0 {name=l43 lab=VDD}
C {madvlsi/gnd.sym} 490 -900 0 0 {name=l44 lab=GND}
C {devices/lab_pin.sym} 150 -980 0 0 {name=p18 sig_type=std_logic lab=PRE}
C {devices/lab_pin.sym} 570 -980 3 0 {name=p64 sig_type=std_logic lab=PREb}
C {madvlsi/pmos3.sym} 1880 -1000 1 1 {name=M153
L=0.15
W=1
body=VDD
nf=1
mult=1
ad="'int((nf+1)/2) * W/nf * 0.29'" 
pd="'2*int((nf+1)/2) * (W/nf + 0.29)'"
as="'int((nf+2)/2) * W/nf * 0.29'" 
ps="'2*int((nf+2)/2) * (W/nf + 0.29)'"
nrd="'0.29 / W'" nrs="'0.29 / W'"
sa=0 sb=0 sd=0
model=pfet_01v8
spiceprefix=X
}
C {madvlsi/nmos3.sym} 1880 -900 3 0 {name=M154
L=0.15
W=1
body=GND
nf=1
mult=1
ad="'int((nf+1)/2) * W/nf * 0.29'" 
pd="'2*int((nf+1)/2) * (W/nf + 0.29)'"
as="'int((nf+2)/2) * W/nf * 0.29'" 
ps="'2*int((nf+2)/2) * (W/nf + 0.29)'"
nrd="'0.29 / W'" nrs="'0.29 / W'"
sa=0 sb=0 sd=0
model=nfet_01v8
spiceprefix=X
}
C {madvlsi/vdd.sym} 1930 -1000 0 0 {name=l45 lab=VDD}
C {madvlsi/gnd.sym} 1930 -900 0 0 {name=l46 lab=GND}
C {madvlsi/pmos3.sym} 2840 -1810 1 1 {name=M155
L=0.15
W=1
body=VDD
nf=1
mult=1
ad="'int((nf+1)/2) * W/nf * 0.29'" 
pd="'2*int((nf+1)/2) * (W/nf + 0.29)'"
as="'int((nf+2)/2) * W/nf * 0.29'" 
ps="'2*int((nf+2)/2) * (W/nf + 0.29)'"
nrd="'0.29 / W'" nrs="'0.29 / W'"
sa=0 sb=0 sd=0
model=pfet_01v8
spiceprefix=X
}
C {madvlsi/nmos3.sym} 2840 -1670 1 0 {name=M156
L=0.15
W=1
body=GND
nf=1
mult=1
ad="'int((nf+1)/2) * W/nf * 0.29'" 
pd="'2*int((nf+1)/2) * (W/nf + 0.29)'"
as="'int((nf+2)/2) * W/nf * 0.29'" 
ps="'2*int((nf+2)/2) * (W/nf + 0.29)'"
nrd="'0.29 / W'" nrs="'0.29 / W'"
sa=0 sb=0 sd=0
model=nfet_01v8
spiceprefix=X
}
C {madvlsi/vdd.sym} 2890 -1810 0 0 {name=l47 lab=VDD}
C {madvlsi/gnd.sym} 2890 -1670 0 0 {name=l48 lab=GND}
C {madvlsi/pmos3.sym} 1680 -1720 2 1 {name=M157
L=0.15
W=1
body=VDD
nf=1
mult=1
ad="'int((nf+1)/2) * W/nf * 0.29'" 
pd="'2*int((nf+1)/2) * (W/nf + 0.29)'"
as="'int((nf+2)/2) * W/nf * 0.29'" 
ps="'2*int((nf+2)/2) * (W/nf + 0.29)'"
nrd="'0.29 / W'" nrs="'0.29 / W'"
sa=0 sb=0 sd=0
model=pfet_01v8
spiceprefix=X
}
C {madvlsi/nmos3.sym} 1680 -1620 0 0 {name=M158
L=0.15
W=1
body=GND
nf=1
mult=1
ad="'int((nf+1)/2) * W/nf * 0.29'" 
pd="'2*int((nf+1)/2) * (W/nf + 0.29)'"
as="'int((nf+2)/2) * W/nf * 0.29'" 
ps="'2*int((nf+2)/2) * (W/nf + 0.29)'"
nrd="'0.29 / W'" nrs="'0.29 / W'"
sa=0 sb=0 sd=0
model=nfet_01v8
spiceprefix=X
}
C {madvlsi/vdd.sym} 1680 -1750 0 0 {name=l49 lab=VDD}
C {madvlsi/gnd.sym} 1680 -1590 0 0 {name=l50 lab=GND}
C {devices/lab_pin.sym} 1700 -1670 2 0 {name=p65 sig_type=std_logic lab=ENADb}
C {devices/lab_pin.sym} 1630 -1670 0 0 {name=p70 sig_type=std_logic lab=ENAD}
C {madvlsi/vdd.sym} 1240 -1130 0 0 {name=l41 lab=VDD}
C {madvlsi/vdd.sym} 2590 -1140 0 0 {name=l27 lab=VDD}
C {madvlsi/vdd.sym} 2800 -1140 0 0 {name=l42 lab=VDD}
C {madvlsi/gnd.sym} 2500 -830 0 0 {name=l51 lab=GND}
C {madvlsi/gnd.sym} 2870 -830 0 0 {name=l52 lab=GND}
C {madvlsi/gnd.sym} 940 -820 0 0 {name=l33 lab=GND}
C {madvlsi/gnd.sym} 1310 -820 0 0 {name=l53 lab=GND}
C {madvlsi/gnd.sym} 1100 -950 0 0 {name=l54 lab=GND}
C {madvlsi/gnd.sym} 2800 -370 0 0 {name=l19 lab=GND}
C {madvlsi/gnd.sym} 2780 -320 0 0 {name=l24 lab=GND}
C {madvlsi/gnd.sym} 2800 -90 0 0 {name=l55 lab=GND}
C {madvlsi/gnd.sym} 2780 -40 0 0 {name=l56 lab=GND}
C {madvlsi/gnd.sym} 2930 -90 0 0 {name=l57 lab=GND}
C {madvlsi/gnd.sym} 2910 -40 0 0 {name=l58 lab=GND}
C {madvlsi/gnd.sym} 3090 -90 0 0 {name=l59 lab=GND}
C {madvlsi/gnd.sym} 3070 -40 0 0 {name=l60 lab=GND}
C {sky130_fd_pr/res_xhigh_po_0p35.sym} 2800 -400 0 0 {name=R5
L=0.385
model=res_xhigh_po_0p35
spiceprefix=X
mult=1}
C {sky130_fd_pr/res_xhigh_po_0p35.sym} 2800 -120 0 0 {name=R1
L=0.42
model=res_xhigh_po_0p35
spiceprefix=X
mult=1}
C {sky130_fd_pr/res_xhigh_po_0p35.sym} 2930 -120 0 0 {name=R2
L=0.42
model=res_xhigh_po_0p35
spiceprefix=X
mult=1}
C {sky130_fd_pr/res_xhigh_po_0p35.sym} 3090 -120 0 0 {name=R3
L=0.42
model=res_xhigh_po_0p35
spiceprefix=X
mult=1}
